VERSION 5.8 ;
BUSBITCHARS "[]" ;
DIVIDERCHAR "/" ;
UNITS
    DATABASE MICRONS 1000 ;
END UNITS

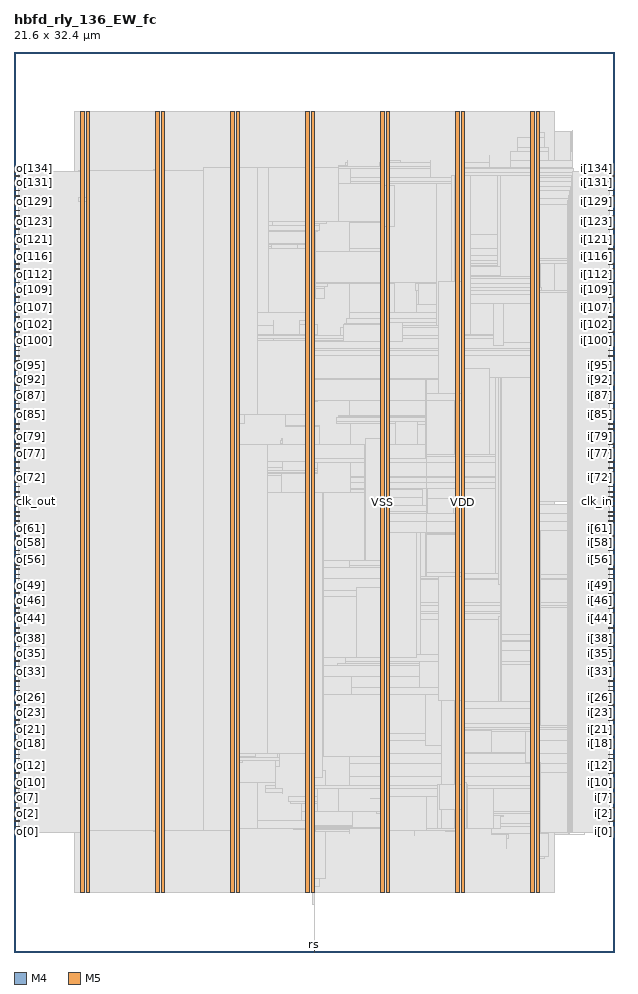
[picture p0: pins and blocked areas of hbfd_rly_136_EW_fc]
MACRO hbfd_rly_136_EW_fc
  FOREIGN hbfd_rly_136_EW_fc 0 0 ;
  CLASS BLOCK ;
  SIZE 21.6 BY 32.4 ;
  PIN clk_in
    DIRECTION INPUT ;
    USE SIGNAL ;
    PORT
      LAYER M4 ;
        RECT  21.408 16.224 21.6 16.248 ;
    END
  END clk_in
  PIN clk_out
    DIRECTION OUTPUT ;
    USE SIGNAL ;
    PORT
      LAYER M4 ;
        RECT  0 16.224 0.192 16.248 ;
    END
  END clk_out
  PIN i[0]
    DIRECTION INPUT ;
    USE SIGNAL ;
    PORT
      LAYER M4 ;
        RECT  21.408 4.32 21.6 4.344 ;
    END
  END i[0]
  PIN i[100]
    DIRECTION INPUT ;
    USE SIGNAL ;
    PORT
      LAYER M4 ;
        RECT  21.408 21.984 21.6 22.008 ;
    END
  END i[100]
  PIN i[101]
    DIRECTION INPUT ;
    USE SIGNAL ;
    PORT
      LAYER M4 ;
        RECT  21.408 22.128 21.6 22.152 ;
    END
  END i[101]
  PIN i[102]
    DIRECTION INPUT ;
    USE SIGNAL ;
    PORT
      LAYER M4 ;
        RECT  21.408 22.32 21.6 22.344 ;
    END
  END i[102]
  PIN i[103]
    DIRECTION INPUT ;
    USE SIGNAL ;
    PORT
      LAYER M4 ;
        RECT  21.408 22.512 21.6 22.536 ;
    END
  END i[103]
  PIN i[104]
    DIRECTION INPUT ;
    USE SIGNAL ;
    PORT
      LAYER M4 ;
        RECT  21.408 22.656 21.6 22.68 ;
    END
  END i[104]
  PIN i[105]
    DIRECTION INPUT ;
    USE SIGNAL ;
    PORT
      LAYER M4 ;
        RECT  21.408 22.848 21.6 22.872 ;
    END
  END i[105]
  PIN i[106]
    DIRECTION INPUT ;
    USE SIGNAL ;
    PORT
      LAYER M4 ;
        RECT  21.408 23.04 21.6 23.064 ;
    END
  END i[106]
  PIN i[107]
    DIRECTION INPUT ;
    USE SIGNAL ;
    PORT
      LAYER M4 ;
        RECT  21.408 23.184 21.6 23.208 ;
    END
  END i[107]
  PIN i[108]
    DIRECTION INPUT ;
    USE SIGNAL ;
    PORT
      LAYER M4 ;
        RECT  21.408 23.376 21.6 23.4 ;
    END
  END i[108]
  PIN i[109]
    DIRECTION INPUT ;
    USE SIGNAL ;
    PORT
      LAYER M4 ;
        RECT  21.408 23.568 21.6 23.592 ;
    END
  END i[109]
  PIN i[10]
    DIRECTION INPUT ;
    USE SIGNAL ;
    PORT
      LAYER M4 ;
        RECT  21.408 6.096 21.6 6.12 ;
    END
  END i[10]
  PIN i[110]
    DIRECTION INPUT ;
    USE SIGNAL ;
    PORT
      LAYER M4 ;
        RECT  21.408 23.712 21.6 23.736 ;
    END
  END i[110]
  PIN i[111]
    DIRECTION INPUT ;
    USE SIGNAL ;
    PORT
      LAYER M4 ;
        RECT  21.408 23.904 21.6 23.928 ;
    END
  END i[111]
  PIN i[112]
    DIRECTION INPUT ;
    USE SIGNAL ;
    PORT
      LAYER M4 ;
        RECT  21.408 24.096 21.6 24.12 ;
    END
  END i[112]
  PIN i[113]
    DIRECTION INPUT ;
    USE SIGNAL ;
    PORT
      LAYER M4 ;
        RECT  21.408 24.24 21.6 24.264 ;
    END
  END i[113]
  PIN i[114]
    DIRECTION INPUT ;
    USE SIGNAL ;
    PORT
      LAYER M4 ;
        RECT  21.408 24.432 21.6 24.456 ;
    END
  END i[114]
  PIN i[115]
    DIRECTION INPUT ;
    USE SIGNAL ;
    PORT
      LAYER M4 ;
        RECT  21.408 24.576 21.6 24.6 ;
    END
  END i[115]
  PIN i[116]
    DIRECTION INPUT ;
    USE SIGNAL ;
    PORT
      LAYER M4 ;
        RECT  21.408 24.768 21.6 24.792 ;
    END
  END i[116]
  PIN i[117]
    DIRECTION INPUT ;
    USE SIGNAL ;
    PORT
      LAYER M4 ;
        RECT  21.408 24.96 21.6 24.984 ;
    END
  END i[117]
  PIN i[118]
    DIRECTION INPUT ;
    USE SIGNAL ;
    PORT
      LAYER M4 ;
        RECT  21.408 25.104 21.6 25.128 ;
    END
  END i[118]
  PIN i[119]
    DIRECTION INPUT ;
    USE SIGNAL ;
    PORT
      LAYER M4 ;
        RECT  21.408 25.296 21.6 25.32 ;
    END
  END i[119]
  PIN i[11]
    DIRECTION INPUT ;
    USE SIGNAL ;
    PORT
      LAYER M4 ;
        RECT  21.408 6.24 21.6 6.264 ;
    END
  END i[11]
  PIN i[120]
    DIRECTION INPUT ;
    USE SIGNAL ;
    PORT
      LAYER M4 ;
        RECT  21.408 25.488 21.6 25.512 ;
    END
  END i[120]
  PIN i[121]
    DIRECTION INPUT ;
    USE SIGNAL ;
    PORT
      LAYER M4 ;
        RECT  21.408 25.632 21.6 25.656 ;
    END
  END i[121]
  PIN i[122]
    DIRECTION INPUT ;
    USE SIGNAL ;
    PORT
      LAYER M4 ;
        RECT  21.408 25.824 21.6 25.848 ;
    END
  END i[122]
  PIN i[123]
    DIRECTION INPUT ;
    USE SIGNAL ;
    PORT
      LAYER M4 ;
        RECT  21.408 26.016 21.6 26.04 ;
    END
  END i[123]
  PIN i[124]
    DIRECTION INPUT ;
    USE SIGNAL ;
    PORT
      LAYER M4 ;
        RECT  21.408 26.16 21.6 26.184 ;
    END
  END i[124]
  PIN i[125]
    DIRECTION INPUT ;
    USE SIGNAL ;
    PORT
      LAYER M4 ;
        RECT  21.408 26.352 21.6 26.376 ;
    END
  END i[125]
  PIN i[126]
    DIRECTION INPUT ;
    USE SIGNAL ;
    PORT
      LAYER M4 ;
        RECT  21.408 26.496 21.6 26.52 ;
    END
  END i[126]
  PIN i[127]
    DIRECTION INPUT ;
    USE SIGNAL ;
    PORT
      LAYER M4 ;
        RECT  21.408 26.688 21.6 26.712 ;
    END
  END i[127]
  PIN i[128]
    DIRECTION INPUT ;
    USE SIGNAL ;
    PORT
      LAYER M4 ;
        RECT  21.408 26.88 21.6 26.904 ;
    END
  END i[128]
  PIN i[129]
    DIRECTION INPUT ;
    USE SIGNAL ;
    PORT
      LAYER M4 ;
        RECT  21.408 27.024 21.6 27.048 ;
    END
  END i[129]
  PIN i[12]
    DIRECTION INPUT ;
    USE SIGNAL ;
    PORT
      LAYER M4 ;
        RECT  21.408 6.432 21.6 6.456 ;
    END
  END i[12]
  PIN i[130]
    DIRECTION INPUT ;
    USE SIGNAL ;
    PORT
      LAYER M4 ;
        RECT  21.408 27.216 21.6 27.24 ;
    END
  END i[130]
  PIN i[131]
    DIRECTION INPUT ;
    USE SIGNAL ;
    PORT
      LAYER M4 ;
        RECT  21.408 27.408 21.6 27.432 ;
    END
  END i[131]
  PIN i[132]
    DIRECTION INPUT ;
    USE SIGNAL ;
    PORT
      LAYER M4 ;
        RECT  21.408 27.552 21.6 27.576 ;
    END
  END i[132]
  PIN i[133]
    DIRECTION INPUT ;
    USE SIGNAL ;
    PORT
      LAYER M4 ;
        RECT  21.408 27.744 21.6 27.768 ;
    END
  END i[133]
  PIN i[134]
    DIRECTION INPUT ;
    USE SIGNAL ;
    PORT
      LAYER M4 ;
        RECT  21.408 27.936 21.6 27.96 ;
    END
  END i[134]
  PIN i[135]
    DIRECTION INPUT ;
    USE SIGNAL ;
    PORT
      LAYER M4 ;
        RECT  21.408 28.08 21.6 28.104 ;
    END
  END i[135]
  PIN i[13]
    DIRECTION INPUT ;
    USE SIGNAL ;
    PORT
      LAYER M4 ;
        RECT  21.408 6.624 21.6 6.648 ;
    END
  END i[13]
  PIN i[14]
    DIRECTION INPUT ;
    USE SIGNAL ;
    PORT
      LAYER M4 ;
        RECT  21.408 6.768 21.6 6.792 ;
    END
  END i[14]
  PIN i[15]
    DIRECTION INPUT ;
    USE SIGNAL ;
    PORT
      LAYER M4 ;
        RECT  21.408 6.96 21.6 6.984 ;
    END
  END i[15]
  PIN i[16]
    DIRECTION INPUT ;
    USE SIGNAL ;
    PORT
      LAYER M4 ;
        RECT  21.408 7.104 21.6 7.128 ;
    END
  END i[16]
  PIN i[17]
    DIRECTION INPUT ;
    USE SIGNAL ;
    PORT
      LAYER M4 ;
        RECT  21.408 7.296 21.6 7.32 ;
    END
  END i[17]
  PIN i[18]
    DIRECTION INPUT ;
    USE SIGNAL ;
    PORT
      LAYER M4 ;
        RECT  21.408 7.488 21.6 7.512 ;
    END
  END i[18]
  PIN i[19]
    DIRECTION INPUT ;
    USE SIGNAL ;
    PORT
      LAYER M4 ;
        RECT  21.408 7.632 21.6 7.656 ;
    END
  END i[19]
  PIN i[1]
    DIRECTION INPUT ;
    USE SIGNAL ;
    PORT
      LAYER M4 ;
        RECT  21.408 4.512 21.6 4.536 ;
    END
  END i[1]
  PIN i[20]
    DIRECTION INPUT ;
    USE SIGNAL ;
    PORT
      LAYER M4 ;
        RECT  21.408 7.824 21.6 7.848 ;
    END
  END i[20]
  PIN i[21]
    DIRECTION INPUT ;
    USE SIGNAL ;
    PORT
      LAYER M4 ;
        RECT  21.408 8.016 21.6 8.04 ;
    END
  END i[21]
  PIN i[22]
    DIRECTION INPUT ;
    USE SIGNAL ;
    PORT
      LAYER M4 ;
        RECT  21.408 8.16 21.6 8.184 ;
    END
  END i[22]
  PIN i[23]
    DIRECTION INPUT ;
    USE SIGNAL ;
    PORT
      LAYER M4 ;
        RECT  21.408 8.352 21.6 8.376 ;
    END
  END i[23]
  PIN i[24]
    DIRECTION INPUT ;
    USE SIGNAL ;
    PORT
      LAYER M4 ;
        RECT  21.408 8.544 21.6 8.568 ;
    END
  END i[24]
  PIN i[25]
    DIRECTION INPUT ;
    USE SIGNAL ;
    PORT
      LAYER M4 ;
        RECT  21.408 8.688 21.6 8.712 ;
    END
  END i[25]
  PIN i[26]
    DIRECTION INPUT ;
    USE SIGNAL ;
    PORT
      LAYER M4 ;
        RECT  21.408 8.88 21.6 8.904 ;
    END
  END i[26]
  PIN i[27]
    DIRECTION INPUT ;
    USE SIGNAL ;
    PORT
      LAYER M4 ;
        RECT  21.408 9.072 21.6 9.096 ;
    END
  END i[27]
  PIN i[28]
    DIRECTION INPUT ;
    USE SIGNAL ;
    PORT
      LAYER M4 ;
        RECT  21.408 9.216 21.6 9.24 ;
    END
  END i[28]
  PIN i[29]
    DIRECTION INPUT ;
    USE SIGNAL ;
    PORT
      LAYER M4 ;
        RECT  21.408 9.408 21.6 9.432 ;
    END
  END i[29]
  PIN i[2]
    DIRECTION INPUT ;
    USE SIGNAL ;
    PORT
      LAYER M4 ;
        RECT  21.408 4.704 21.6 4.728 ;
    END
  END i[2]
  PIN i[30]
    DIRECTION INPUT ;
    USE SIGNAL ;
    PORT
      LAYER M4 ;
        RECT  21.408 9.552 21.6 9.576 ;
    END
  END i[30]
  PIN i[31]
    DIRECTION INPUT ;
    USE SIGNAL ;
    PORT
      LAYER M4 ;
        RECT  21.408 9.744 21.6 9.768 ;
    END
  END i[31]
  PIN i[32]
    DIRECTION INPUT ;
    USE SIGNAL ;
    PORT
      LAYER M4 ;
        RECT  21.408 9.936 21.6 9.96 ;
    END
  END i[32]
  PIN i[33]
    DIRECTION INPUT ;
    USE SIGNAL ;
    PORT
      LAYER M4 ;
        RECT  21.408 10.08 21.6 10.104 ;
    END
  END i[33]
  PIN i[34]
    DIRECTION INPUT ;
    USE SIGNAL ;
    PORT
      LAYER M4 ;
        RECT  21.408 10.272 21.6 10.296 ;
    END
  END i[34]
  PIN i[35]
    DIRECTION INPUT ;
    USE SIGNAL ;
    PORT
      LAYER M4 ;
        RECT  21.408 10.464 21.6 10.488 ;
    END
  END i[35]
  PIN i[36]
    DIRECTION INPUT ;
    USE SIGNAL ;
    PORT
      LAYER M4 ;
        RECT  21.408 10.608 21.6 10.632 ;
    END
  END i[36]
  PIN i[37]
    DIRECTION INPUT ;
    USE SIGNAL ;
    PORT
      LAYER M4 ;
        RECT  21.408 10.8 21.6 10.824 ;
    END
  END i[37]
  PIN i[38]
    DIRECTION INPUT ;
    USE SIGNAL ;
    PORT
      LAYER M4 ;
        RECT  21.408 10.992 21.6 11.016 ;
    END
  END i[38]
  PIN i[39]
    DIRECTION INPUT ;
    USE SIGNAL ;
    PORT
      LAYER M4 ;
        RECT  21.408 11.136 21.6 11.16 ;
    END
  END i[39]
  PIN i[3]
    DIRECTION INPUT ;
    USE SIGNAL ;
    PORT
      LAYER M4 ;
        RECT  21.408 4.848 21.6 4.872 ;
    END
  END i[3]
  PIN i[40]
    DIRECTION INPUT ;
    USE SIGNAL ;
    PORT
      LAYER M4 ;
        RECT  21.408 11.328 21.6 11.352 ;
    END
  END i[40]
  PIN i[41]
    DIRECTION INPUT ;
    USE SIGNAL ;
    PORT
      LAYER M4 ;
        RECT  21.408 11.472 21.6 11.496 ;
    END
  END i[41]
  PIN i[42]
    DIRECTION INPUT ;
    USE SIGNAL ;
    PORT
      LAYER M4 ;
        RECT  21.408 11.664 21.6 11.688 ;
    END
  END i[42]
  PIN i[43]
    DIRECTION INPUT ;
    USE SIGNAL ;
    PORT
      LAYER M4 ;
        RECT  21.408 11.856 21.6 11.88 ;
    END
  END i[43]
  PIN i[44]
    DIRECTION INPUT ;
    USE SIGNAL ;
    PORT
      LAYER M4 ;
        RECT  21.408 12 21.6 12.024 ;
    END
  END i[44]
  PIN i[45]
    DIRECTION INPUT ;
    USE SIGNAL ;
    PORT
      LAYER M4 ;
        RECT  21.408 12.192 21.6 12.216 ;
    END
  END i[45]
  PIN i[46]
    DIRECTION INPUT ;
    USE SIGNAL ;
    PORT
      LAYER M4 ;
        RECT  21.408 12.384 21.6 12.408 ;
    END
  END i[46]
  PIN i[47]
    DIRECTION INPUT ;
    USE SIGNAL ;
    PORT
      LAYER M4 ;
        RECT  21.408 12.528 21.6 12.552 ;
    END
  END i[47]
  PIN i[48]
    DIRECTION INPUT ;
    USE SIGNAL ;
    PORT
      LAYER M4 ;
        RECT  21.408 12.72 21.6 12.744 ;
    END
  END i[48]
  PIN i[49]
    DIRECTION INPUT ;
    USE SIGNAL ;
    PORT
      LAYER M4 ;
        RECT  21.408 12.912 21.6 12.936 ;
    END
  END i[49]
  PIN i[4]
    DIRECTION INPUT ;
    USE SIGNAL ;
    PORT
      LAYER M4 ;
        RECT  21.408 5.04 21.6 5.064 ;
    END
  END i[4]
  PIN i[50]
    DIRECTION INPUT ;
    USE SIGNAL ;
    PORT
      LAYER M4 ;
        RECT  21.408 13.056 21.6 13.08 ;
    END
  END i[50]
  PIN i[51]
    DIRECTION INPUT ;
    USE SIGNAL ;
    PORT
      LAYER M4 ;
        RECT  21.408 13.248 21.6 13.272 ;
    END
  END i[51]
  PIN i[52]
    DIRECTION INPUT ;
    USE SIGNAL ;
    PORT
      LAYER M4 ;
        RECT  21.408 13.44 21.6 13.464 ;
    END
  END i[52]
  PIN i[53]
    DIRECTION INPUT ;
    USE SIGNAL ;
    PORT
      LAYER M4 ;
        RECT  21.408 13.584 21.6 13.608 ;
    END
  END i[53]
  PIN i[54]
    DIRECTION INPUT ;
    USE SIGNAL ;
    PORT
      LAYER M4 ;
        RECT  21.408 13.776 21.6 13.8 ;
    END
  END i[54]
  PIN i[55]
    DIRECTION INPUT ;
    USE SIGNAL ;
    PORT
      LAYER M4 ;
        RECT  21.408 13.92 21.6 13.944 ;
    END
  END i[55]
  PIN i[56]
    DIRECTION INPUT ;
    USE SIGNAL ;
    PORT
      LAYER M4 ;
        RECT  21.408 14.112 21.6 14.136 ;
    END
  END i[56]
  PIN i[57]
    DIRECTION INPUT ;
    USE SIGNAL ;
    PORT
      LAYER M4 ;
        RECT  21.408 14.304 21.6 14.328 ;
    END
  END i[57]
  PIN i[58]
    DIRECTION INPUT ;
    USE SIGNAL ;
    PORT
      LAYER M4 ;
        RECT  21.408 14.448 21.6 14.472 ;
    END
  END i[58]
  PIN i[59]
    DIRECTION INPUT ;
    USE SIGNAL ;
    PORT
      LAYER M4 ;
        RECT  21.408 14.64 21.6 14.664 ;
    END
  END i[59]
  PIN i[5]
    DIRECTION INPUT ;
    USE SIGNAL ;
    PORT
      LAYER M4 ;
        RECT  21.408 5.184 21.6 5.208 ;
    END
  END i[5]
  PIN i[60]
    DIRECTION INPUT ;
    USE SIGNAL ;
    PORT
      LAYER M4 ;
        RECT  21.408 14.832 21.6 14.856 ;
    END
  END i[60]
  PIN i[61]
    DIRECTION INPUT ;
    USE SIGNAL ;
    PORT
      LAYER M4 ;
        RECT  21.408 14.976 21.6 15 ;
    END
  END i[61]
  PIN i[62]
    DIRECTION INPUT ;
    USE SIGNAL ;
    PORT
      LAYER M4 ;
        RECT  21.408 15.168 21.6 15.192 ;
    END
  END i[62]
  PIN i[63]
    DIRECTION INPUT ;
    USE SIGNAL ;
    PORT
      LAYER M4 ;
        RECT  21.408 15.36 21.6 15.384 ;
    END
  END i[63]
  PIN i[64]
    DIRECTION INPUT ;
    USE SIGNAL ;
    PORT
      LAYER M4 ;
        RECT  21.408 15.504 21.6 15.528 ;
    END
  END i[64]
  PIN i[65]
    DIRECTION INPUT ;
    USE SIGNAL ;
    PORT
      LAYER M4 ;
        RECT  21.408 15.696 21.6 15.72 ;
    END
  END i[65]
  PIN i[66]
    DIRECTION INPUT ;
    USE SIGNAL ;
    PORT
      LAYER M4 ;
        RECT  21.408 15.84 21.6 15.864 ;
    END
  END i[66]
  PIN i[67]
    DIRECTION INPUT ;
    USE SIGNAL ;
    PORT
      LAYER M4 ;
        RECT  21.408 16.032 21.6 16.056 ;
    END
  END i[67]
  PIN i[68]
    DIRECTION INPUT ;
    USE SIGNAL ;
    PORT
      LAYER M4 ;
        RECT  21.408 16.368 21.6 16.392 ;
    END
  END i[68]
  PIN i[69]
    DIRECTION INPUT ;
    USE SIGNAL ;
    PORT
      LAYER M4 ;
        RECT  21.408 16.56 21.6 16.584 ;
    END
  END i[69]
  PIN i[6]
    DIRECTION INPUT ;
    USE SIGNAL ;
    PORT
      LAYER M4 ;
        RECT  21.408 5.376 21.6 5.4 ;
    END
  END i[6]
  PIN i[70]
    DIRECTION INPUT ;
    USE SIGNAL ;
    PORT
      LAYER M4 ;
        RECT  21.408 16.752 21.6 16.776 ;
    END
  END i[70]
  PIN i[71]
    DIRECTION INPUT ;
    USE SIGNAL ;
    PORT
      LAYER M4 ;
        RECT  21.408 16.896 21.6 16.92 ;
    END
  END i[71]
  PIN i[72]
    DIRECTION INPUT ;
    USE SIGNAL ;
    PORT
      LAYER M4 ;
        RECT  21.408 17.088 21.6 17.112 ;
    END
  END i[72]
  PIN i[73]
    DIRECTION INPUT ;
    USE SIGNAL ;
    PORT
      LAYER M4 ;
        RECT  21.408 17.28 21.6 17.304 ;
    END
  END i[73]
  PIN i[74]
    DIRECTION INPUT ;
    USE SIGNAL ;
    PORT
      LAYER M4 ;
        RECT  21.408 17.424 21.6 17.448 ;
    END
  END i[74]
  PIN i[75]
    DIRECTION INPUT ;
    USE SIGNAL ;
    PORT
      LAYER M4 ;
        RECT  21.408 17.616 21.6 17.64 ;
    END
  END i[75]
  PIN i[76]
    DIRECTION INPUT ;
    USE SIGNAL ;
    PORT
      LAYER M4 ;
        RECT  21.408 17.808 21.6 17.832 ;
    END
  END i[76]
  PIN i[77]
    DIRECTION INPUT ;
    USE SIGNAL ;
    PORT
      LAYER M4 ;
        RECT  21.408 17.952 21.6 17.976 ;
    END
  END i[77]
  PIN i[78]
    DIRECTION INPUT ;
    USE SIGNAL ;
    PORT
      LAYER M4 ;
        RECT  21.408 18.144 21.6 18.168 ;
    END
  END i[78]
  PIN i[79]
    DIRECTION INPUT ;
    USE SIGNAL ;
    PORT
      LAYER M4 ;
        RECT  21.408 18.288 21.6 18.312 ;
    END
  END i[79]
  PIN i[7]
    DIRECTION INPUT ;
    USE SIGNAL ;
    PORT
      LAYER M4 ;
        RECT  21.408 5.568 21.6 5.592 ;
    END
  END i[7]
  PIN i[80]
    DIRECTION INPUT ;
    USE SIGNAL ;
    PORT
      LAYER M4 ;
        RECT  21.408 18.48 21.6 18.504 ;
    END
  END i[80]
  PIN i[81]
    DIRECTION INPUT ;
    USE SIGNAL ;
    PORT
      LAYER M4 ;
        RECT  21.408 18.672 21.6 18.696 ;
    END
  END i[81]
  PIN i[82]
    DIRECTION INPUT ;
    USE SIGNAL ;
    PORT
      LAYER M4 ;
        RECT  21.408 18.816 21.6 18.84 ;
    END
  END i[82]
  PIN i[83]
    DIRECTION INPUT ;
    USE SIGNAL ;
    PORT
      LAYER M4 ;
        RECT  21.408 19.008 21.6 19.032 ;
    END
  END i[83]
  PIN i[84]
    DIRECTION INPUT ;
    USE SIGNAL ;
    PORT
      LAYER M4 ;
        RECT  21.408 19.2 21.6 19.224 ;
    END
  END i[84]
  PIN i[85]
    DIRECTION INPUT ;
    USE SIGNAL ;
    PORT
      LAYER M4 ;
        RECT  21.408 19.344 21.6 19.368 ;
    END
  END i[85]
  PIN i[86]
    DIRECTION INPUT ;
    USE SIGNAL ;
    PORT
      LAYER M4 ;
        RECT  21.408 19.536 21.6 19.56 ;
    END
  END i[86]
  PIN i[87]
    DIRECTION INPUT ;
    USE SIGNAL ;
    PORT
      LAYER M4 ;
        RECT  21.408 19.728 21.6 19.752 ;
    END
  END i[87]
  PIN i[88]
    DIRECTION INPUT ;
    USE SIGNAL ;
    PORT
      LAYER M4 ;
        RECT  21.408 19.872 21.6 19.896 ;
    END
  END i[88]
  PIN i[89]
    DIRECTION INPUT ;
    USE SIGNAL ;
    PORT
      LAYER M4 ;
        RECT  21.408 20.064 21.6 20.088 ;
    END
  END i[89]
  PIN i[8]
    DIRECTION INPUT ;
    USE SIGNAL ;
    PORT
      LAYER M4 ;
        RECT  21.408 5.712 21.6 5.736 ;
    END
  END i[8]
  PIN i[90]
    DIRECTION INPUT ;
    USE SIGNAL ;
    PORT
      LAYER M4 ;
        RECT  21.408 20.208 21.6 20.232 ;
    END
  END i[90]
  PIN i[91]
    DIRECTION INPUT ;
    USE SIGNAL ;
    PORT
      LAYER M4 ;
        RECT  21.408 20.4 21.6 20.424 ;
    END
  END i[91]
  PIN i[92]
    DIRECTION INPUT ;
    USE SIGNAL ;
    PORT
      LAYER M4 ;
        RECT  21.408 20.592 21.6 20.616 ;
    END
  END i[92]
  PIN i[93]
    DIRECTION INPUT ;
    USE SIGNAL ;
    PORT
      LAYER M4 ;
        RECT  21.408 20.736 21.6 20.76 ;
    END
  END i[93]
  PIN i[94]
    DIRECTION INPUT ;
    USE SIGNAL ;
    PORT
      LAYER M4 ;
        RECT  21.408 20.928 21.6 20.952 ;
    END
  END i[94]
  PIN i[95]
    DIRECTION INPUT ;
    USE SIGNAL ;
    PORT
      LAYER M4 ;
        RECT  21.408 21.12 21.6 21.144 ;
    END
  END i[95]
  PIN i[96]
    DIRECTION INPUT ;
    USE SIGNAL ;
    PORT
      LAYER M4 ;
        RECT  21.408 21.264 21.6 21.288 ;
    END
  END i[96]
  PIN i[97]
    DIRECTION INPUT ;
    USE SIGNAL ;
    PORT
      LAYER M4 ;
        RECT  21.408 21.456 21.6 21.48 ;
    END
  END i[97]
  PIN i[98]
    DIRECTION INPUT ;
    USE SIGNAL ;
    PORT
      LAYER M4 ;
        RECT  21.408 21.648 21.6 21.672 ;
    END
  END i[98]
  PIN i[99]
    DIRECTION INPUT ;
    USE SIGNAL ;
    PORT
      LAYER M4 ;
        RECT  21.408 21.792 21.6 21.816 ;
    END
  END i[99]
  PIN i[9]
    DIRECTION INPUT ;
    USE SIGNAL ;
    PORT
      LAYER M4 ;
        RECT  21.408 5.904 21.6 5.928 ;
    END
  END i[9]
  PIN o[0]
    DIRECTION OUTPUT ;
    USE SIGNAL ;
    PORT
      LAYER M4 ;
        RECT  0 4.32 0.192 4.344 ;
    END
  END o[0]
  PIN o[100]
    DIRECTION OUTPUT ;
    USE SIGNAL ;
    PORT
      LAYER M4 ;
        RECT  0 21.984 0.192 22.008 ;
    END
  END o[100]
  PIN o[101]
    DIRECTION OUTPUT ;
    USE SIGNAL ;
    PORT
      LAYER M4 ;
        RECT  0 22.128 0.192 22.152 ;
    END
  END o[101]
  PIN o[102]
    DIRECTION OUTPUT ;
    USE SIGNAL ;
    PORT
      LAYER M4 ;
        RECT  0 22.32 0.192 22.344 ;
    END
  END o[102]
  PIN o[103]
    DIRECTION OUTPUT ;
    USE SIGNAL ;
    PORT
      LAYER M4 ;
        RECT  0 22.512 0.192 22.536 ;
    END
  END o[103]
  PIN o[104]
    DIRECTION OUTPUT ;
    USE SIGNAL ;
    PORT
      LAYER M4 ;
        RECT  0 22.656 0.192 22.68 ;
    END
  END o[104]
  PIN o[105]
    DIRECTION OUTPUT ;
    USE SIGNAL ;
    PORT
      LAYER M4 ;
        RECT  0 22.848 0.192 22.872 ;
    END
  END o[105]
  PIN o[106]
    DIRECTION OUTPUT ;
    USE SIGNAL ;
    PORT
      LAYER M4 ;
        RECT  0 23.04 0.192 23.064 ;
    END
  END o[106]
  PIN o[107]
    DIRECTION OUTPUT ;
    USE SIGNAL ;
    PORT
      LAYER M4 ;
        RECT  0 23.184 0.192 23.208 ;
    END
  END o[107]
  PIN o[108]
    DIRECTION OUTPUT ;
    USE SIGNAL ;
    PORT
      LAYER M4 ;
        RECT  0 23.376 0.192 23.4 ;
    END
  END o[108]
  PIN o[109]
    DIRECTION OUTPUT ;
    USE SIGNAL ;
    PORT
      LAYER M4 ;
        RECT  0 23.568 0.192 23.592 ;
    END
  END o[109]
  PIN o[10]
    DIRECTION OUTPUT ;
    USE SIGNAL ;
    PORT
      LAYER M4 ;
        RECT  0 6.096 0.192 6.12 ;
    END
  END o[10]
  PIN o[110]
    DIRECTION OUTPUT ;
    USE SIGNAL ;
    PORT
      LAYER M4 ;
        RECT  0 23.712 0.192 23.736 ;
    END
  END o[110]
  PIN o[111]
    DIRECTION OUTPUT ;
    USE SIGNAL ;
    PORT
      LAYER M4 ;
        RECT  0 23.904 0.192 23.928 ;
    END
  END o[111]
  PIN o[112]
    DIRECTION OUTPUT ;
    USE SIGNAL ;
    PORT
      LAYER M4 ;
        RECT  0 24.096 0.192 24.12 ;
    END
  END o[112]
  PIN o[113]
    DIRECTION OUTPUT ;
    USE SIGNAL ;
    PORT
      LAYER M4 ;
        RECT  0 24.24 0.192 24.264 ;
    END
  END o[113]
  PIN o[114]
    DIRECTION OUTPUT ;
    USE SIGNAL ;
    PORT
      LAYER M4 ;
        RECT  0 24.432 0.192 24.456 ;
    END
  END o[114]
  PIN o[115]
    DIRECTION OUTPUT ;
    USE SIGNAL ;
    PORT
      LAYER M4 ;
        RECT  0 24.576 0.192 24.6 ;
    END
  END o[115]
  PIN o[116]
    DIRECTION OUTPUT ;
    USE SIGNAL ;
    PORT
      LAYER M4 ;
        RECT  0 24.768 0.192 24.792 ;
    END
  END o[116]
  PIN o[117]
    DIRECTION OUTPUT ;
    USE SIGNAL ;
    PORT
      LAYER M4 ;
        RECT  0 24.96 0.192 24.984 ;
    END
  END o[117]
  PIN o[118]
    DIRECTION OUTPUT ;
    USE SIGNAL ;
    PORT
      LAYER M4 ;
        RECT  0 25.104 0.192 25.128 ;
    END
  END o[118]
  PIN o[119]
    DIRECTION OUTPUT ;
    USE SIGNAL ;
    PORT
      LAYER M4 ;
        RECT  0 25.296 0.192 25.32 ;
    END
  END o[119]
  PIN o[11]
    DIRECTION OUTPUT ;
    USE SIGNAL ;
    PORT
      LAYER M4 ;
        RECT  0 6.24 0.192 6.264 ;
    END
  END o[11]
  PIN o[120]
    DIRECTION OUTPUT ;
    USE SIGNAL ;
    PORT
      LAYER M4 ;
        RECT  0 25.488 0.192 25.512 ;
    END
  END o[120]
  PIN o[121]
    DIRECTION OUTPUT ;
    USE SIGNAL ;
    PORT
      LAYER M4 ;
        RECT  0 25.632 0.192 25.656 ;
    END
  END o[121]
  PIN o[122]
    DIRECTION OUTPUT ;
    USE SIGNAL ;
    PORT
      LAYER M4 ;
        RECT  0 25.824 0.192 25.848 ;
    END
  END o[122]
  PIN o[123]
    DIRECTION OUTPUT ;
    USE SIGNAL ;
    PORT
      LAYER M4 ;
        RECT  0 26.016 0.192 26.04 ;
    END
  END o[123]
  PIN o[124]
    DIRECTION OUTPUT ;
    USE SIGNAL ;
    PORT
      LAYER M4 ;
        RECT  0 26.16 0.192 26.184 ;
    END
  END o[124]
  PIN o[125]
    DIRECTION OUTPUT ;
    USE SIGNAL ;
    PORT
      LAYER M4 ;
        RECT  0 26.352 0.192 26.376 ;
    END
  END o[125]
  PIN o[126]
    DIRECTION OUTPUT ;
    USE SIGNAL ;
    PORT
      LAYER M4 ;
        RECT  0 26.496 0.192 26.52 ;
    END
  END o[126]
  PIN o[127]
    DIRECTION OUTPUT ;
    USE SIGNAL ;
    PORT
      LAYER M4 ;
        RECT  0 26.688 0.192 26.712 ;
    END
  END o[127]
  PIN o[128]
    DIRECTION OUTPUT ;
    USE SIGNAL ;
    PORT
      LAYER M4 ;
        RECT  0 26.88 0.192 26.904 ;
    END
  END o[128]
  PIN o[129]
    DIRECTION OUTPUT ;
    USE SIGNAL ;
    PORT
      LAYER M4 ;
        RECT  0 27.024 0.192 27.048 ;
    END
  END o[129]
  PIN o[12]
    DIRECTION OUTPUT ;
    USE SIGNAL ;
    PORT
      LAYER M4 ;
        RECT  0 6.432 0.192 6.456 ;
    END
  END o[12]
  PIN o[130]
    DIRECTION OUTPUT ;
    USE SIGNAL ;
    PORT
      LAYER M4 ;
        RECT  0 27.216 0.192 27.24 ;
    END
  END o[130]
  PIN o[131]
    DIRECTION OUTPUT ;
    USE SIGNAL ;
    PORT
      LAYER M4 ;
        RECT  0 27.408 0.192 27.432 ;
    END
  END o[131]
  PIN o[132]
    DIRECTION OUTPUT ;
    USE SIGNAL ;
    PORT
      LAYER M4 ;
        RECT  0 27.552 0.192 27.576 ;
    END
  END o[132]
  PIN o[133]
    DIRECTION OUTPUT ;
    USE SIGNAL ;
    PORT
      LAYER M4 ;
        RECT  0 27.744 0.192 27.768 ;
    END
  END o[133]
  PIN o[134]
    DIRECTION OUTPUT ;
    USE SIGNAL ;
    PORT
      LAYER M4 ;
        RECT  0 27.936 0.192 27.96 ;
    END
  END o[134]
  PIN o[135]
    DIRECTION OUTPUT ;
    USE SIGNAL ;
    PORT
      LAYER M4 ;
        RECT  0 28.08 0.192 28.104 ;
    END
  END o[135]
  PIN o[13]
    DIRECTION OUTPUT ;
    USE SIGNAL ;
    PORT
      LAYER M4 ;
        RECT  0 6.624 0.192 6.648 ;
    END
  END o[13]
  PIN o[14]
    DIRECTION OUTPUT ;
    USE SIGNAL ;
    PORT
      LAYER M4 ;
        RECT  0 6.768 0.192 6.792 ;
    END
  END o[14]
  PIN o[15]
    DIRECTION OUTPUT ;
    USE SIGNAL ;
    PORT
      LAYER M4 ;
        RECT  0 6.96 0.192 6.984 ;
    END
  END o[15]
  PIN o[16]
    DIRECTION OUTPUT ;
    USE SIGNAL ;
    PORT
      LAYER M4 ;
        RECT  0 7.104 0.192 7.128 ;
    END
  END o[16]
  PIN o[17]
    DIRECTION OUTPUT ;
    USE SIGNAL ;
    PORT
      LAYER M4 ;
        RECT  0 7.296 0.192 7.32 ;
    END
  END o[17]
  PIN o[18]
    DIRECTION OUTPUT ;
    USE SIGNAL ;
    PORT
      LAYER M4 ;
        RECT  0 7.488 0.192 7.512 ;
    END
  END o[18]
  PIN o[19]
    DIRECTION OUTPUT ;
    USE SIGNAL ;
    PORT
      LAYER M4 ;
        RECT  0 7.632 0.192 7.656 ;
    END
  END o[19]
  PIN o[1]
    DIRECTION OUTPUT ;
    USE SIGNAL ;
    PORT
      LAYER M4 ;
        RECT  0 4.512 0.192 4.536 ;
    END
  END o[1]
  PIN o[20]
    DIRECTION OUTPUT ;
    USE SIGNAL ;
    PORT
      LAYER M4 ;
        RECT  0 7.824 0.192 7.848 ;
    END
  END o[20]
  PIN o[21]
    DIRECTION OUTPUT ;
    USE SIGNAL ;
    PORT
      LAYER M4 ;
        RECT  0 8.016 0.192 8.04 ;
    END
  END o[21]
  PIN o[22]
    DIRECTION OUTPUT ;
    USE SIGNAL ;
    PORT
      LAYER M4 ;
        RECT  0 8.16 0.192 8.184 ;
    END
  END o[22]
  PIN o[23]
    DIRECTION OUTPUT ;
    USE SIGNAL ;
    PORT
      LAYER M4 ;
        RECT  0 8.352 0.192 8.376 ;
    END
  END o[23]
  PIN o[24]
    DIRECTION OUTPUT ;
    USE SIGNAL ;
    PORT
      LAYER M4 ;
        RECT  0 8.544 0.192 8.568 ;
    END
  END o[24]
  PIN o[25]
    DIRECTION OUTPUT ;
    USE SIGNAL ;
    PORT
      LAYER M4 ;
        RECT  0 8.688 0.192 8.712 ;
    END
  END o[25]
  PIN o[26]
    DIRECTION OUTPUT ;
    USE SIGNAL ;
    PORT
      LAYER M4 ;
        RECT  0 8.88 0.192 8.904 ;
    END
  END o[26]
  PIN o[27]
    DIRECTION OUTPUT ;
    USE SIGNAL ;
    PORT
      LAYER M4 ;
        RECT  0 9.072 0.192 9.096 ;
    END
  END o[27]
  PIN o[28]
    DIRECTION OUTPUT ;
    USE SIGNAL ;
    PORT
      LAYER M4 ;
        RECT  0 9.216 0.192 9.24 ;
    END
  END o[28]
  PIN o[29]
    DIRECTION OUTPUT ;
    USE SIGNAL ;
    PORT
      LAYER M4 ;
        RECT  0 9.408 0.192 9.432 ;
    END
  END o[29]
  PIN o[2]
    DIRECTION OUTPUT ;
    USE SIGNAL ;
    PORT
      LAYER M4 ;
        RECT  0 4.704 0.192 4.728 ;
    END
  END o[2]
  PIN o[30]
    DIRECTION OUTPUT ;
    USE SIGNAL ;
    PORT
      LAYER M4 ;
        RECT  0 9.552 0.192 9.576 ;
    END
  END o[30]
  PIN o[31]
    DIRECTION OUTPUT ;
    USE SIGNAL ;
    PORT
      LAYER M4 ;
        RECT  0 9.744 0.192 9.768 ;
    END
  END o[31]
  PIN o[32]
    DIRECTION OUTPUT ;
    USE SIGNAL ;
    PORT
      LAYER M4 ;
        RECT  0 9.936 0.192 9.96 ;
    END
  END o[32]
  PIN o[33]
    DIRECTION OUTPUT ;
    USE SIGNAL ;
    PORT
      LAYER M4 ;
        RECT  0 10.08 0.192 10.104 ;
    END
  END o[33]
  PIN o[34]
    DIRECTION OUTPUT ;
    USE SIGNAL ;
    PORT
      LAYER M4 ;
        RECT  0 10.272 0.192 10.296 ;
    END
  END o[34]
  PIN o[35]
    DIRECTION OUTPUT ;
    USE SIGNAL ;
    PORT
      LAYER M4 ;
        RECT  0 10.464 0.192 10.488 ;
    END
  END o[35]
  PIN o[36]
    DIRECTION OUTPUT ;
    USE SIGNAL ;
    PORT
      LAYER M4 ;
        RECT  0 10.608 0.192 10.632 ;
    END
  END o[36]
  PIN o[37]
    DIRECTION OUTPUT ;
    USE SIGNAL ;
    PORT
      LAYER M4 ;
        RECT  0 10.8 0.192 10.824 ;
    END
  END o[37]
  PIN o[38]
    DIRECTION OUTPUT ;
    USE SIGNAL ;
    PORT
      LAYER M4 ;
        RECT  0 10.992 0.192 11.016 ;
    END
  END o[38]
  PIN o[39]
    DIRECTION OUTPUT ;
    USE SIGNAL ;
    PORT
      LAYER M4 ;
        RECT  0 11.136 0.192 11.16 ;
    END
  END o[39]
  PIN o[3]
    DIRECTION OUTPUT ;
    USE SIGNAL ;
    PORT
      LAYER M4 ;
        RECT  0 4.848 0.192 4.872 ;
    END
  END o[3]
  PIN o[40]
    DIRECTION OUTPUT ;
    USE SIGNAL ;
    PORT
      LAYER M4 ;
        RECT  0 11.328 0.192 11.352 ;
    END
  END o[40]
  PIN o[41]
    DIRECTION OUTPUT ;
    USE SIGNAL ;
    PORT
      LAYER M4 ;
        RECT  0 11.472 0.192 11.496 ;
    END
  END o[41]
  PIN o[42]
    DIRECTION OUTPUT ;
    USE SIGNAL ;
    PORT
      LAYER M4 ;
        RECT  0 11.664 0.192 11.688 ;
    END
  END o[42]
  PIN o[43]
    DIRECTION OUTPUT ;
    USE SIGNAL ;
    PORT
      LAYER M4 ;
        RECT  0 11.856 0.192 11.88 ;
    END
  END o[43]
  PIN o[44]
    DIRECTION OUTPUT ;
    USE SIGNAL ;
    PORT
      LAYER M4 ;
        RECT  0 12 0.192 12.024 ;
    END
  END o[44]
  PIN o[45]
    DIRECTION OUTPUT ;
    USE SIGNAL ;
    PORT
      LAYER M4 ;
        RECT  0 12.192 0.192 12.216 ;
    END
  END o[45]
  PIN o[46]
    DIRECTION OUTPUT ;
    USE SIGNAL ;
    PORT
      LAYER M4 ;
        RECT  0 12.384 0.192 12.408 ;
    END
  END o[46]
  PIN o[47]
    DIRECTION OUTPUT ;
    USE SIGNAL ;
    PORT
      LAYER M4 ;
        RECT  0 12.528 0.192 12.552 ;
    END
  END o[47]
  PIN o[48]
    DIRECTION OUTPUT ;
    USE SIGNAL ;
    PORT
      LAYER M4 ;
        RECT  0 12.72 0.192 12.744 ;
    END
  END o[48]
  PIN o[49]
    DIRECTION OUTPUT ;
    USE SIGNAL ;
    PORT
      LAYER M4 ;
        RECT  0 12.912 0.192 12.936 ;
    END
  END o[49]
  PIN o[4]
    DIRECTION OUTPUT ;
    USE SIGNAL ;
    PORT
      LAYER M4 ;
        RECT  0 5.04 0.192 5.064 ;
    END
  END o[4]
  PIN o[50]
    DIRECTION OUTPUT ;
    USE SIGNAL ;
    PORT
      LAYER M4 ;
        RECT  0 13.056 0.192 13.08 ;
    END
  END o[50]
  PIN o[51]
    DIRECTION OUTPUT ;
    USE SIGNAL ;
    PORT
      LAYER M4 ;
        RECT  0 13.248 0.192 13.272 ;
    END
  END o[51]
  PIN o[52]
    DIRECTION OUTPUT ;
    USE SIGNAL ;
    PORT
      LAYER M4 ;
        RECT  0 13.44 0.192 13.464 ;
    END
  END o[52]
  PIN o[53]
    DIRECTION OUTPUT ;
    USE SIGNAL ;
    PORT
      LAYER M4 ;
        RECT  0 13.584 0.192 13.608 ;
    END
  END o[53]
  PIN o[54]
    DIRECTION OUTPUT ;
    USE SIGNAL ;
    PORT
      LAYER M4 ;
        RECT  0 13.776 0.192 13.8 ;
    END
  END o[54]
  PIN o[55]
    DIRECTION OUTPUT ;
    USE SIGNAL ;
    PORT
      LAYER M4 ;
        RECT  0 13.92 0.192 13.944 ;
    END
  END o[55]
  PIN o[56]
    DIRECTION OUTPUT ;
    USE SIGNAL ;
    PORT
      LAYER M4 ;
        RECT  0 14.112 0.192 14.136 ;
    END
  END o[56]
  PIN o[57]
    DIRECTION OUTPUT ;
    USE SIGNAL ;
    PORT
      LAYER M4 ;
        RECT  0 14.304 0.192 14.328 ;
    END
  END o[57]
  PIN o[58]
    DIRECTION OUTPUT ;
    USE SIGNAL ;
    PORT
      LAYER M4 ;
        RECT  0 14.448 0.192 14.472 ;
    END
  END o[58]
  PIN o[59]
    DIRECTION OUTPUT ;
    USE SIGNAL ;
    PORT
      LAYER M4 ;
        RECT  0 14.64 0.192 14.664 ;
    END
  END o[59]
  PIN o[5]
    DIRECTION OUTPUT ;
    USE SIGNAL ;
    PORT
      LAYER M4 ;
        RECT  0 5.184 0.192 5.208 ;
    END
  END o[5]
  PIN o[60]
    DIRECTION OUTPUT ;
    USE SIGNAL ;
    PORT
      LAYER M4 ;
        RECT  0 14.832 0.192 14.856 ;
    END
  END o[60]
  PIN o[61]
    DIRECTION OUTPUT ;
    USE SIGNAL ;
    PORT
      LAYER M4 ;
        RECT  0 14.976 0.192 15 ;
    END
  END o[61]
  PIN o[62]
    DIRECTION OUTPUT ;
    USE SIGNAL ;
    PORT
      LAYER M4 ;
        RECT  0 15.168 0.192 15.192 ;
    END
  END o[62]
  PIN o[63]
    DIRECTION OUTPUT ;
    USE SIGNAL ;
    PORT
      LAYER M4 ;
        RECT  0 15.36 0.192 15.384 ;
    END
  END o[63]
  PIN o[64]
    DIRECTION OUTPUT ;
    USE SIGNAL ;
    PORT
      LAYER M4 ;
        RECT  0 15.504 0.192 15.528 ;
    END
  END o[64]
  PIN o[65]
    DIRECTION OUTPUT ;
    USE SIGNAL ;
    PORT
      LAYER M4 ;
        RECT  0 15.696 0.192 15.72 ;
    END
  END o[65]
  PIN o[66]
    DIRECTION OUTPUT ;
    USE SIGNAL ;
    PORT
      LAYER M4 ;
        RECT  0 15.84 0.192 15.864 ;
    END
  END o[66]
  PIN o[67]
    DIRECTION OUTPUT ;
    USE SIGNAL ;
    PORT
      LAYER M4 ;
        RECT  0 16.032 0.192 16.056 ;
    END
  END o[67]
  PIN o[68]
    DIRECTION OUTPUT ;
    USE SIGNAL ;
    PORT
      LAYER M4 ;
        RECT  0 16.368 0.192 16.392 ;
    END
  END o[68]
  PIN o[69]
    DIRECTION OUTPUT ;
    USE SIGNAL ;
    PORT
      LAYER M4 ;
        RECT  0 16.56 0.192 16.584 ;
    END
  END o[69]
  PIN o[6]
    DIRECTION OUTPUT ;
    USE SIGNAL ;
    PORT
      LAYER M4 ;
        RECT  0 5.376 0.192 5.4 ;
    END
  END o[6]
  PIN o[70]
    DIRECTION OUTPUT ;
    USE SIGNAL ;
    PORT
      LAYER M4 ;
        RECT  0 16.752 0.192 16.776 ;
    END
  END o[70]
  PIN o[71]
    DIRECTION OUTPUT ;
    USE SIGNAL ;
    PORT
      LAYER M4 ;
        RECT  0 16.896 0.192 16.92 ;
    END
  END o[71]
  PIN o[72]
    DIRECTION OUTPUT ;
    USE SIGNAL ;
    PORT
      LAYER M4 ;
        RECT  0 17.088 0.192 17.112 ;
    END
  END o[72]
  PIN o[73]
    DIRECTION OUTPUT ;
    USE SIGNAL ;
    PORT
      LAYER M4 ;
        RECT  0 17.28 0.192 17.304 ;
    END
  END o[73]
  PIN o[74]
    DIRECTION OUTPUT ;
    USE SIGNAL ;
    PORT
      LAYER M4 ;
        RECT  0 17.424 0.192 17.448 ;
    END
  END o[74]
  PIN o[75]
    DIRECTION OUTPUT ;
    USE SIGNAL ;
    PORT
      LAYER M4 ;
        RECT  0 17.616 0.192 17.64 ;
    END
  END o[75]
  PIN o[76]
    DIRECTION OUTPUT ;
    USE SIGNAL ;
    PORT
      LAYER M4 ;
        RECT  0 17.808 0.192 17.832 ;
    END
  END o[76]
  PIN o[77]
    DIRECTION OUTPUT ;
    USE SIGNAL ;
    PORT
      LAYER M4 ;
        RECT  0 17.952 0.192 17.976 ;
    END
  END o[77]
  PIN o[78]
    DIRECTION OUTPUT ;
    USE SIGNAL ;
    PORT
      LAYER M4 ;
        RECT  0 18.144 0.192 18.168 ;
    END
  END o[78]
  PIN o[79]
    DIRECTION OUTPUT ;
    USE SIGNAL ;
    PORT
      LAYER M4 ;
        RECT  0 18.288 0.192 18.312 ;
    END
  END o[79]
  PIN o[7]
    DIRECTION OUTPUT ;
    USE SIGNAL ;
    PORT
      LAYER M4 ;
        RECT  0 5.568 0.192 5.592 ;
    END
  END o[7]
  PIN o[80]
    DIRECTION OUTPUT ;
    USE SIGNAL ;
    PORT
      LAYER M4 ;
        RECT  0 18.48 0.192 18.504 ;
    END
  END o[80]
  PIN o[81]
    DIRECTION OUTPUT ;
    USE SIGNAL ;
    PORT
      LAYER M4 ;
        RECT  0 18.672 0.192 18.696 ;
    END
  END o[81]
  PIN o[82]
    DIRECTION OUTPUT ;
    USE SIGNAL ;
    PORT
      LAYER M4 ;
        RECT  0 18.816 0.192 18.84 ;
    END
  END o[82]
  PIN o[83]
    DIRECTION OUTPUT ;
    USE SIGNAL ;
    PORT
      LAYER M4 ;
        RECT  0 19.008 0.192 19.032 ;
    END
  END o[83]
  PIN o[84]
    DIRECTION OUTPUT ;
    USE SIGNAL ;
    PORT
      LAYER M4 ;
        RECT  0 19.2 0.192 19.224 ;
    END
  END o[84]
  PIN o[85]
    DIRECTION OUTPUT ;
    USE SIGNAL ;
    PORT
      LAYER M4 ;
        RECT  0 19.344 0.192 19.368 ;
    END
  END o[85]
  PIN o[86]
    DIRECTION OUTPUT ;
    USE SIGNAL ;
    PORT
      LAYER M4 ;
        RECT  0 19.536 0.192 19.56 ;
    END
  END o[86]
  PIN o[87]
    DIRECTION OUTPUT ;
    USE SIGNAL ;
    PORT
      LAYER M4 ;
        RECT  0 19.728 0.192 19.752 ;
    END
  END o[87]
  PIN o[88]
    DIRECTION OUTPUT ;
    USE SIGNAL ;
    PORT
      LAYER M4 ;
        RECT  0 19.872 0.192 19.896 ;
    END
  END o[88]
  PIN o[89]
    DIRECTION OUTPUT ;
    USE SIGNAL ;
    PORT
      LAYER M4 ;
        RECT  0 20.064 0.192 20.088 ;
    END
  END o[89]
  PIN o[8]
    DIRECTION OUTPUT ;
    USE SIGNAL ;
    PORT
      LAYER M4 ;
        RECT  0 5.712 0.192 5.736 ;
    END
  END o[8]
  PIN o[90]
    DIRECTION OUTPUT ;
    USE SIGNAL ;
    PORT
      LAYER M4 ;
        RECT  0 20.208 0.192 20.232 ;
    END
  END o[90]
  PIN o[91]
    DIRECTION OUTPUT ;
    USE SIGNAL ;
    PORT
      LAYER M4 ;
        RECT  0 20.4 0.192 20.424 ;
    END
  END o[91]
  PIN o[92]
    DIRECTION OUTPUT ;
    USE SIGNAL ;
    PORT
      LAYER M4 ;
        RECT  0 20.592 0.192 20.616 ;
    END
  END o[92]
  PIN o[93]
    DIRECTION OUTPUT ;
    USE SIGNAL ;
    PORT
      LAYER M4 ;
        RECT  0 20.736 0.192 20.76 ;
    END
  END o[93]
  PIN o[94]
    DIRECTION OUTPUT ;
    USE SIGNAL ;
    PORT
      LAYER M4 ;
        RECT  0 20.928 0.192 20.952 ;
    END
  END o[94]
  PIN o[95]
    DIRECTION OUTPUT ;
    USE SIGNAL ;
    PORT
      LAYER M4 ;
        RECT  0 21.12 0.192 21.144 ;
    END
  END o[95]
  PIN o[96]
    DIRECTION OUTPUT ;
    USE SIGNAL ;
    PORT
      LAYER M4 ;
        RECT  0 21.264 0.192 21.288 ;
    END
  END o[96]
  PIN o[97]
    DIRECTION OUTPUT ;
    USE SIGNAL ;
    PORT
      LAYER M4 ;
        RECT  0 21.456 0.192 21.48 ;
    END
  END o[97]
  PIN o[98]
    DIRECTION OUTPUT ;
    USE SIGNAL ;
    PORT
      LAYER M4 ;
        RECT  0 21.648 0.192 21.672 ;
    END
  END o[98]
  PIN o[99]
    DIRECTION OUTPUT ;
    USE SIGNAL ;
    PORT
      LAYER M4 ;
        RECT  0 21.792 0.192 21.816 ;
    END
  END o[99]
  PIN o[9]
    DIRECTION OUTPUT ;
    USE SIGNAL ;
    PORT
      LAYER M4 ;
        RECT  0 5.904 0.192 5.928 ;
    END
  END o[9]
  PIN rs
    DIRECTION INPUT ;
    USE SIGNAL ;
    PORT
      LAYER M5 ;
        RECT  10.8 0 10.824 0.192 ;
    END
  END rs
  PIN VDD
    DIRECTION INOUT ;
    USE POWER ;
    PORT
      LAYER M5 ;
        RECT  18.792 2.151 18.912 30.249 ;
        RECT  16.092 2.151 16.212 30.249 ;
        RECT  13.392 2.151 13.512 30.249 ;
        RECT  10.692 2.151 10.812 30.249 ;
        RECT  7.992 2.151 8.112 30.249 ;
        RECT  5.292 2.151 5.412 30.249 ;
        RECT  2.592 2.151 2.712 30.249 ;
    END
  END VDD
  PIN VSS
    DIRECTION INOUT ;
    USE GROUND ;
    PORT
      LAYER M5 ;
        RECT  18.6 2.137 18.72 30.263 ;
        RECT  15.9 2.137 16.02 30.263 ;
        RECT  13.2 2.137 13.32 30.263 ;
        RECT  10.5 2.137 10.62 30.263 ;
        RECT  7.8 2.137 7.92 30.263 ;
        RECT  5.1 2.137 5.22 30.263 ;
        RECT  2.4 2.137 2.52 30.263 ;
    END
  END VSS
  OBS
    LAYER RVTN ;
     RECT  2.16 2.16 19.44 2.295 ;
     RECT  2.16 2.565 19.44 2.835 ;
     RECT  2.16 3.105 19.44 3.375 ;
     RECT  2.16 3.645 19.44 3.915 ;
     RECT  2.16 4.185 19.44 4.455 ;
     RECT  2.16 4.725 19.44 4.995 ;
     RECT  2.16 5.265 19.44 5.535 ;
     RECT  2.16 5.805 19.44 6.075 ;
     RECT  2.16 6.345 19.44 6.615 ;
     RECT  2.16 6.885 19.44 7.155 ;
     RECT  2.16 7.425 19.44 7.695 ;
     RECT  2.16 7.965 19.44 8.235 ;
     RECT  2.16 8.505 19.44 8.775 ;
     RECT  2.16 9.045 19.44 9.315 ;
     RECT  2.16 9.585 19.44 9.855 ;
     RECT  2.16 10.125 19.44 10.395 ;
     RECT  2.16 10.665 19.44 10.935 ;
     RECT  2.16 11.205 19.44 11.475 ;
     RECT  2.16 11.745 19.44 12.015 ;
     RECT  2.16 12.285 19.44 12.555 ;
     RECT  2.16 12.825 19.44 13.095 ;
     RECT  2.16 13.365 19.44 13.635 ;
     RECT  2.16 13.905 19.44 14.175 ;
     RECT  2.16 14.445 19.44 14.715 ;
     RECT  2.16 14.985 19.44 15.255 ;
     RECT  2.16 15.525 19.44 15.795 ;
     RECT  2.16 16.065 19.44 16.335 ;
     RECT  2.16 16.605 19.44 16.875 ;
     RECT  2.16 17.145 19.44 17.415 ;
     RECT  2.16 17.685 19.44 17.955 ;
     RECT  2.16 18.225 19.44 18.495 ;
     RECT  2.16 18.765 19.44 19.035 ;
     RECT  2.16 19.305 19.44 19.575 ;
     RECT  2.16 19.845 19.44 20.115 ;
     RECT  2.16 20.385 19.44 20.655 ;
     RECT  2.16 20.925 19.44 21.195 ;
     RECT  2.16 21.465 19.44 21.735 ;
     RECT  2.16 22.005 19.44 22.275 ;
     RECT  2.16 22.545 19.44 22.815 ;
     RECT  2.16 23.085 19.44 23.355 ;
     RECT  2.16 23.625 19.44 23.895 ;
     RECT  2.16 24.165 19.44 24.435 ;
     RECT  2.16 24.705 19.44 24.975 ;
     RECT  2.16 25.245 19.44 25.515 ;
     RECT  2.16 25.785 19.44 26.055 ;
     RECT  2.16 26.325 19.44 26.595 ;
     RECT  2.16 26.865 19.44 27.135 ;
     RECT  2.16 27.405 19.44 27.675 ;
     RECT  2.16 27.945 19.44 28.215 ;
     RECT  2.16 28.485 19.44 28.755 ;
     RECT  2.16 29.025 19.44 29.295 ;
     RECT  2.16 29.565 19.44 29.835 ;
     RECT  2.16 30.105 19.44 30.24 ;
    LAYER RVTP ;
     RECT  2.16 2.295 19.44 2.565 ;
     RECT  2.16 2.835 19.44 3.105 ;
     RECT  2.16 3.375 19.44 3.645 ;
     RECT  2.16 3.915 19.44 4.185 ;
     RECT  2.16 4.455 19.44 4.725 ;
     RECT  2.16 4.995 19.44 5.265 ;
     RECT  2.16 5.535 19.44 5.805 ;
     RECT  2.16 6.075 19.44 6.345 ;
     RECT  2.16 6.615 19.44 6.885 ;
     RECT  2.16 7.155 19.44 7.425 ;
     RECT  2.16 7.695 19.44 7.965 ;
     RECT  2.16 8.235 19.44 8.505 ;
     RECT  2.16 8.775 19.44 9.045 ;
     RECT  2.16 9.315 19.44 9.585 ;
     RECT  2.16 9.855 19.44 10.125 ;
     RECT  2.16 10.395 19.44 10.665 ;
     RECT  2.16 10.935 19.44 11.205 ;
     RECT  2.16 11.475 19.44 11.745 ;
     RECT  2.16 12.015 19.44 12.285 ;
     RECT  2.16 12.555 19.44 12.825 ;
     RECT  2.16 13.095 19.44 13.365 ;
     RECT  2.16 13.635 19.44 13.905 ;
     RECT  2.16 14.175 19.44 14.445 ;
     RECT  2.16 14.715 19.44 14.985 ;
     RECT  2.16 15.255 19.44 15.525 ;
     RECT  2.16 15.795 19.44 16.065 ;
     RECT  2.16 16.335 19.44 16.605 ;
     RECT  2.16 16.875 19.44 17.145 ;
     RECT  2.16 17.415 19.44 17.685 ;
     RECT  2.16 17.955 19.44 18.225 ;
     RECT  2.16 18.495 19.44 18.765 ;
     RECT  2.16 19.035 19.44 19.305 ;
     RECT  2.16 19.575 19.44 19.845 ;
     RECT  2.16 20.115 19.44 20.385 ;
     RECT  2.16 20.655 19.44 20.925 ;
     RECT  2.16 21.195 19.44 21.465 ;
     RECT  2.16 21.735 19.44 22.005 ;
     RECT  2.16 22.275 19.44 22.545 ;
     RECT  2.16 22.815 19.44 23.085 ;
     RECT  2.16 23.355 19.44 23.625 ;
     RECT  2.16 23.895 19.44 24.165 ;
     RECT  2.16 24.435 19.44 24.705 ;
     RECT  2.16 24.975 19.44 25.245 ;
     RECT  2.16 25.515 19.44 25.785 ;
     RECT  2.16 26.055 19.44 26.325 ;
     RECT  2.16 26.595 19.44 26.865 ;
     RECT  2.16 27.135 19.44 27.405 ;
     RECT  2.16 27.675 19.44 27.945 ;
     RECT  2.16 28.215 19.44 28.485 ;
     RECT  2.16 28.755 19.44 29.025 ;
     RECT  2.16 29.295 19.44 29.565 ;
     RECT  2.16 29.835 19.44 30.105 ;
    LAYER M1 ;
     RECT  2.16 2.151 19.44 30.249 ;
    LAYER M2 ;
     RECT  0.211 5.814 0.247 6.444 ;
     RECT  0.211 9.396 0.247 10.314 ;
     RECT  0.211 19.008 0.247 19.026 ;
     RECT  0.211 7.326 0.499 7.344 ;
     RECT  0.247 19.008 0.499 19.764 ;
     RECT  0.463 4.464 0.535 4.482 ;
     RECT  0.247 5.706 0.535 6.444 ;
     RECT  0.499 7.326 0.535 7.794 ;
     RECT  0.211 12.798 0.535 13.824 ;
     RECT  0.211 16.776 0.535 16.938 ;
     RECT  0.499 18.27 0.535 19.764 ;
     RECT  0.499 20.7 0.535 20.718 ;
     RECT  0.499 22.788 0.535 22.806 ;
     RECT  0.535 4.428 2.16 4.482 ;
     RECT  0.535 5.544 2.16 6.444 ;
     RECT  0.535 7.326 2.16 7.956 ;
     RECT  0.247 8.856 2.16 10.314 ;
     RECT  0.535 11.376 2.16 11.394 ;
     RECT  0.535 12.456 2.16 13.824 ;
     RECT  0.211 15.336 2.16 15.354 ;
     RECT  0.535 16.506 2.16 20.718 ;
     RECT  0.535 22.176 2.16 22.806 ;
     RECT  0.211 23.796 2.16 24.084 ;
     RECT  0.247 27.108 2.16 27.126 ;
     RECT  0.535 27.918 2.16 27.936 ;
     RECT  2.16 2.151 19.44 30.249 ;
     RECT  19.44 16.884 19.463 25.236 ;
     RECT  19.44 26.028 19.463 29.556 ;
     RECT  19.44 4.23 19.967 16.128 ;
     RECT  19.463 17.082 19.967 25.236 ;
     RECT  19.463 26.028 19.967 26.856 ;
     RECT  19.967 4.23 20.003 4.482 ;
     RECT  19.967 6.318 20.003 14.778 ;
     RECT  19.967 15.768 20.003 16.128 ;
     RECT  19.967 17.082 20.003 22.608 ;
     RECT  19.967 23.67 20.003 24.768 ;
     RECT  19.967 26.298 20.003 26.658 ;
     RECT  20.003 6.318 20.039 6.336 ;
     RECT  20.003 7.704 20.039 8.226 ;
     RECT  20.003 10.71 20.039 10.89 ;
     RECT  20.003 11.826 20.039 12.51 ;
     RECT  20.003 13.446 20.039 14.706 ;
     RECT  20.003 15.84 20.039 16.128 ;
     RECT  20.003 17.082 20.039 18.216 ;
     RECT  20.003 19.278 20.039 19.296 ;
     RECT  20.003 20.088 20.039 20.448 ;
     RECT  20.003 22.05 20.039 22.068 ;
     RECT  20.003 23.67 20.039 23.688 ;
     RECT  20.003 24.48 20.039 24.498 ;
     RECT  19.463 27.756 20.039 29.556 ;
     RECT  20.003 9.36 20.075 9.846 ;
     RECT  20.039 16.038 20.075 16.128 ;
     RECT  20.039 17.082 20.075 17.478 ;
     RECT  20.039 20.088 20.075 20.106 ;
     RECT  20.039 28.998 20.075 29.556 ;
     RECT  20.039 10.791 20.111 10.89 ;
     RECT  20.039 27.756 20.111 28.206 ;
     RECT  20.075 29.538 20.111 29.556 ;
     RECT  20.111 28.188 20.147 28.206 ;
     RECT  20.003 4.23 20.543 4.248 ;
     RECT  20.075 9.63 20.543 9.846 ;
     RECT  20.111 10.872 20.543 10.89 ;
     RECT  20.039 12.492 20.543 12.51 ;
     RECT  20.039 13.446 20.543 14.004 ;
     RECT  20.075 16.11 20.543 16.128 ;
     RECT  20.075 17.082 20.543 17.1 ;
     RECT  20.543 9.63 20.579 9.648 ;
     RECT  20.543 13.446 20.579 13.464 ;
     RECT  21.379 10.296 21.479 10.314 ;
    LAYER M3 ;
     RECT  10.8 1.723 10.818 2.143 ;
     RECT  10.515 2.143 10.818 2.371 ;
     RECT  2.415 2.143 2.505 2.413 ;
     RECT  5.115 2.143 5.205 2.413 ;
     RECT  7.815 2.143 7.905 2.413 ;
     RECT  13.215 2.143 13.305 2.413 ;
     RECT  15.915 2.143 16.005 2.413 ;
     RECT  18.615 2.143 18.705 2.413 ;
     RECT  10.515 2.371 10.998 2.641 ;
     RECT  18.615 2.413 18.897 3.379 ;
     RECT  18.615 3.379 19.098 3.451 ;
     RECT  17.712 3.721 17.73 4.081 ;
     RECT  17.712 4.081 17.802 4.225 ;
     RECT  17.208 4.225 17.802 4.261 ;
     RECT  18.615 3.451 19.242 4.261 ;
     RECT  2.415 2.413 2.697 4.315 ;
     RECT  5.115 2.413 5.397 4.351 ;
     RECT  10.515 2.641 11.214 4.351 ;
     RECT  12.06 4.261 12.078 4.351 ;
     RECT  15.915 2.413 16.197 4.351 ;
     RECT  14.4 4.189 14.418 4.363 ;
     RECT  15.516 4.351 16.197 4.363 ;
     RECT  10.515 4.351 12.078 4.423 ;
     RECT  0.54 4.423 0.558 4.459 ;
     RECT  10.044 4.423 12.078 4.459 ;
     RECT  20.52 4.225 20.538 4.459 ;
     RECT  10.044 4.459 12.186 4.507 ;
     RECT  17.208 4.261 19.242 4.507 ;
     RECT  19.98 4.459 20.538 4.507 ;
     RECT  13.215 2.413 13.497 4.531 ;
     RECT  14.4 4.363 16.197 4.531 ;
     RECT  17.208 4.507 20.538 4.531 ;
     RECT  9.972 4.507 12.186 4.559 ;
     RECT  13.215 4.531 13.554 4.621 ;
     RECT  14.4 4.531 20.538 4.621 ;
     RECT  0.468 4.459 0.558 4.733 ;
     RECT  13.215 4.621 20.538 4.999 ;
     RECT  10.332 4.559 12.186 5.063 ;
     RECT  13.032 4.999 20.538 5.069 ;
     RECT  11.664 5.063 12.186 5.071 ;
     RECT  13.032 5.069 19.998 5.071 ;
     RECT  6.84 4.363 6.858 5.197 ;
     RECT  6.84 5.197 6.93 5.341 ;
     RECT  10.332 5.063 10.926 5.341 ;
     RECT  5.004 4.351 5.397 5.369 ;
     RECT  6.3 5.341 6.93 5.369 ;
     RECT  2.304 4.315 2.697 5.405 ;
     RECT  7.815 2.413 8.097 5.431 ;
     RECT  9.936 5.341 10.926 5.431 ;
     RECT  6.3 5.369 6.894 5.495 ;
     RECT  0.468 4.733 0.486 5.539 ;
     RECT  0.468 5.539 0.558 5.563 ;
     RECT  6.84 5.495 6.894 5.567 ;
     RECT  9.864 5.431 10.926 5.603 ;
     RECT  7.815 5.431 8.766 5.639 ;
     RECT  9.648 5.701 9.666 5.737 ;
     RECT  9.036 5.737 9.666 5.873 ;
     RECT  10.515 5.603 10.926 5.881 ;
     RECT  11.664 5.071 19.998 5.881 ;
     RECT  9.036 5.873 9.414 5.999 ;
     RECT  10.515 5.881 19.998 5.999 ;
     RECT  6.84 5.567 6.858 6.179 ;
     RECT  12.06 5.999 19.998 6.313 ;
     RECT  0.216 5.563 0.558 6.449 ;
     RECT  0.54 6.449 0.558 6.461 ;
     RECT  10.515 5.999 11.214 6.539 ;
     RECT  7.815 5.639 8.097 6.583 ;
     RECT  5.115 5.369 5.397 6.619 ;
     RECT  3.996 6.619 4.014 6.656 ;
     RECT  4.86 6.619 5.397 6.691 ;
     RECT  9.396 5.999 9.414 6.691 ;
     RECT  12.06 6.313 20.034 6.797 ;
     RECT  7.164 6.583 8.097 6.817 ;
     RECT  4.716 6.691 5.397 6.845 ;
     RECT  6.12 6.511 6.282 6.845 ;
     RECT  7.164 6.817 8.226 6.889 ;
     RECT  9.396 6.691 9.558 6.889 ;
     RECT  2.415 5.405 2.697 6.952 ;
     RECT  7.164 6.889 9.558 6.989 ;
     RECT  7.164 6.989 8.694 7.051 ;
     RECT  12.06 6.797 19.998 7.159 ;
     RECT  9.468 6.989 9.558 7.195 ;
     RECT  0.216 7.291 0.234 7.349 ;
     RECT  9.468 7.195 9.63 7.349 ;
     RECT  2.304 6.952 2.697 7.529 ;
     RECT  10.515 6.539 10.797 7.591 ;
     RECT  5.004 6.845 5.397 7.619 ;
     RECT  5.04 7.619 5.397 7.627 ;
     RECT  11.988 7.159 19.998 7.627 ;
     RECT  6.624 7.051 8.694 7.661 ;
     RECT  10.515 7.591 11.25 7.691 ;
     RECT  5.04 7.627 5.67 7.735 ;
     RECT  6.624 7.661 8.442 7.735 ;
     RECT  5.04 7.735 8.442 7.799 ;
     RECT  2.415 7.529 2.697 7.861 ;
     RECT  5.115 7.799 8.442 7.889 ;
     RECT  0.504 7.771 0.522 7.933 ;
     RECT  6.264 7.889 8.442 7.961 ;
     RECT  11.988 7.627 20.034 8.011 ;
     RECT  10.515 7.691 11.106 8.033 ;
     RECT  9.468 7.349 9.486 8.041 ;
     RECT  0.504 7.933 0.558 8.045 ;
     RECT  11.916 8.011 20.034 8.069 ;
     RECT  6.3 7.961 8.442 8.159 ;
     RECT  0.504 8.045 0.522 8.189 ;
     RECT  12.132 8.069 20.034 8.231 ;
     RECT  5.115 7.889 5.49 8.339 ;
     RECT  9.216 8.041 9.486 8.401 ;
     RECT  10.515 8.033 10.926 8.401 ;
     RECT  9.216 8.401 10.926 8.501 ;
     RECT  9.216 8.501 9.774 8.537 ;
     RECT  2.415 7.861 2.79 8.671 ;
     RECT  7.815 8.159 8.442 8.671 ;
     RECT  2.304 8.671 2.79 8.683 ;
     RECT  12.132 8.231 19.998 8.771 ;
     RECT  2.304 8.683 2.862 8.813 ;
     RECT  6.3 8.159 7.038 8.843 ;
     RECT  6.408 8.843 7.038 8.879 ;
     RECT  0.252 8.851 0.27 8.909 ;
     RECT  6.876 8.879 7.038 8.969 ;
     RECT  7.815 8.671 9.09 8.969 ;
     RECT  6.876 8.969 6.966 9.101 ;
     RECT  5.115 8.339 5.397 9.112 ;
     RECT  5.004 9.112 5.397 9.149 ;
     RECT  2.304 8.813 2.754 9.248 ;
     RECT  10.515 8.501 10.926 9.283 ;
     RECT  6.948 9.101 6.966 9.293 ;
     RECT  19.944 8.771 19.998 9.355 ;
     RECT  8.964 8.969 9.09 9.391 ;
     RECT  2.415 9.248 2.754 9.419 ;
     RECT  12.132 8.771 19.206 9.509 ;
     RECT  19.944 9.355 20.07 9.547 ;
     RECT  8.964 9.391 9.666 9.553 ;
     RECT  8.964 9.553 9.702 9.581 ;
     RECT  19.944 9.547 20.538 9.625 ;
     RECT  9.396 9.581 9.702 9.661 ;
     RECT  15.336 9.509 19.206 9.661 ;
     RECT  19.944 9.625 20.574 9.661 ;
     RECT  9.396 9.661 9.738 9.851 ;
     RECT  6.372 9.823 6.75 9.859 ;
     RECT  10.515 9.283 11.07 9.931 ;
     RECT  12.132 9.509 14.598 9.931 ;
     RECT  7.815 8.969 8.097 10.021 ;
     RECT  6.336 9.859 6.75 10.049 ;
     RECT  9.396 9.851 9.486 10.049 ;
     RECT  7.704 10.021 8.097 10.057 ;
     RECT  15.336 9.661 20.574 10.109 ;
     RECT  7.596 10.057 8.334 10.229 ;
     RECT  21.384 10.267 21.402 10.291 ;
     RECT  10.515 9.931 14.598 10.319 ;
     RECT  21.384 10.291 21.474 10.319 ;
     RECT  21.456 10.319 21.474 10.349 ;
     RECT  7.815 10.229 8.334 10.363 ;
     RECT  11.628 10.319 14.598 10.391 ;
     RECT  5.115 9.149 5.397 10.459 ;
     RECT  11.916 10.391 14.598 10.471 ;
     RECT  15.336 10.109 20.106 10.471 ;
     RECT  5.115 10.459 5.49 10.499 ;
     RECT  9.432 10.049 9.486 10.669 ;
     RECT  10.515 10.319 10.854 10.669 ;
     RECT  0.216 9.391 0.234 10.829 ;
     RECT  11.916 10.471 20.106 10.867 ;
     RECT  9.432 10.669 10.854 11.011 ;
     RECT  7.815 10.363 8.586 11.129 ;
     RECT  9.324 11.011 10.854 11.173 ;
     RECT  11.916 10.867 20.538 11.173 ;
     RECT  6.3 11.137 6.822 11.179 ;
     RECT  9.324 11.173 20.538 11.201 ;
     RECT  5.115 10.499 5.397 11.272 ;
     RECT  2.415 9.419 2.697 11.281 ;
     RECT  6.3 11.179 6.858 11.309 ;
     RECT  6.336 11.309 6.354 11.399 ;
     RECT  7.815 11.129 8.478 11.399 ;
     RECT  0.54 11.371 0.558 11.501 ;
     RECT  9.396 11.201 20.538 11.501 ;
     RECT  7.815 11.399 8.154 11.641 ;
     RECT  7.668 11.641 8.154 11.741 ;
     RECT  7.668 11.741 8.097 11.749 ;
     RECT  2.304 11.281 2.697 11.885 ;
     RECT  5.004 11.272 5.397 11.939 ;
     RECT  7.416 11.749 8.097 11.939 ;
     RECT  6.48 12.055 6.498 12.091 ;
     RECT  5.115 11.939 5.397 12.181 ;
     RECT  9.396 11.501 20.034 12.181 ;
     RECT  6.48 12.091 6.858 12.209 ;
     RECT  9.216 12.181 20.034 12.269 ;
     RECT  6.336 12.289 6.354 12.389 ;
     RECT  0.252 12.235 0.27 12.451 ;
     RECT  5.115 12.181 5.49 12.451 ;
     RECT  9.36 12.269 20.034 12.479 ;
     RECT  9.756 12.479 20.034 12.487 ;
     RECT  0.252 12.451 0.558 12.557 ;
     RECT  9.756 12.487 20.538 12.587 ;
     RECT  2.415 11.885 2.697 12.619 ;
     RECT  2.415 12.619 2.79 12.659 ;
     RECT  5.115 12.451 6.138 12.749 ;
     RECT  7.815 11.939 8.097 12.991 ;
     RECT  9.756 12.587 13.77 13.019 ;
     RECT  7.815 12.991 8.622 13.171 ;
     RECT  9.756 13.019 9.774 13.199 ;
     RECT  5.115 12.749 5.397 13.261 ;
     RECT  6.12 12.749 6.138 13.289 ;
     RECT  4.824 13.261 5.397 13.361 ;
     RECT  2.415 12.659 2.697 13.387 ;
     RECT  7.815 13.171 8.766 13.387 ;
     RECT  14.58 12.587 20.538 13.405 ;
     RECT  2.415 13.387 2.862 13.432 ;
     RECT  7.524 13.387 8.766 13.433 ;
     RECT  2.304 13.432 2.862 13.435 ;
     RECT  10.515 13.019 13.77 13.441 ;
     RECT  14.508 13.405 20.538 13.441 ;
     RECT  2.304 13.435 2.97 13.469 ;
     RECT  7.524 13.433 8.154 13.567 ;
     RECT  2.415 13.469 2.97 13.613 ;
     RECT  0.216 12.793 0.234 13.829 ;
     RECT  10.515 13.441 20.574 13.829 ;
     RECT  6.336 13.801 6.354 13.901 ;
     RECT  12.06 13.829 20.574 13.901 ;
     RECT  7.416 13.567 8.154 13.915 ;
     RECT  10.515 13.829 10.926 13.937 ;
     RECT  19.944 13.901 20.574 13.949 ;
     RECT  19.944 13.949 20.538 14.009 ;
     RECT  9 13.945 9.018 14.071 ;
     RECT  7.056 13.915 8.154 14.099 ;
     RECT  7.524 14.099 8.154 14.171 ;
     RECT  7.815 14.171 8.154 14.251 ;
     RECT  9 14.071 9.09 14.251 ;
     RECT  2.415 13.613 2.697 14.341 ;
     RECT  5.115 13.361 5.397 14.341 ;
     RECT  2.415 14.341 2.79 14.381 ;
     RECT  5.115 14.341 5.49 14.381 ;
     RECT  10.515 13.937 10.854 14.44 ;
     RECT  10.332 14.44 10.854 14.449 ;
     RECT  7.815 14.251 9.09 14.485 ;
     RECT  10.116 14.449 10.854 14.485 ;
     RECT  12.06 13.901 19.17 14.635 ;
     RECT  19.944 14.009 20.034 14.635 ;
     RECT  7.815 14.485 10.854 14.675 ;
     RECT  7.815 14.675 9.09 14.819 ;
     RECT  9.036 14.819 9.09 14.909 ;
     RECT  0.252 14.827 0.27 15.053 ;
     RECT  12.06 14.635 20.034 15.061 ;
     RECT  11.808 15.061 20.034 15.101 ;
     RECT  2.415 14.381 2.697 15.151 ;
     RECT  7.815 14.819 8.097 15.151 ;
     RECT  2.304 15.151 2.697 15.163 ;
     RECT  11.808 15.101 12.078 15.179 ;
     RECT  9.936 14.675 10.854 15.251 ;
     RECT  7.488 15.151 8.097 15.259 ;
     RECT  10.515 15.251 10.854 15.259 ;
     RECT  2.304 15.163 2.862 15.293 ;
     RECT  7.2 15.259 8.097 15.331 ;
     RECT  10.515 15.259 10.926 15.359 ;
     RECT  0.216 15.331 0.234 15.389 ;
     RECT  12.888 15.101 20.034 15.499 ;
     RECT  5.115 14.381 5.397 15.691 ;
     RECT  6.696 15.331 8.097 15.691 ;
     RECT  9.072 14.909 9.09 15.691 ;
     RECT  5.004 15.691 5.397 15.728 ;
     RECT  12.06 15.179 12.078 15.791 ;
     RECT  12.888 15.499 20.538 15.791 ;
     RECT  12.888 15.791 14.886 15.871 ;
     RECT  6.696 15.691 9.09 15.899 ;
     RECT  7.488 15.899 9.09 15.989 ;
     RECT  5.115 15.728 5.397 16.027 ;
     RECT  15.804 15.791 20.538 16.097 ;
     RECT  20.52 16.097 20.538 16.133 ;
     RECT  9 15.989 9.09 16.141 ;
     RECT  10.515 15.359 10.854 16.169 ;
     RECT  2.304 15.293 2.697 16.219 ;
     RECT  9 16.141 9.558 16.231 ;
     RECT  10.515 16.169 10.797 16.231 ;
     RECT  2.304 16.219 2.862 16.259 ;
     RECT  6.624 16.141 6.642 16.259 ;
     RECT  5.115 16.027 5.562 16.267 ;
     RECT  2.415 16.259 2.862 16.339 ;
     RECT  9 16.231 10.797 16.349 ;
     RECT  2.415 16.339 2.898 16.529 ;
     RECT  7.488 15.989 8.19 16.529 ;
     RECT  15.804 16.097 19.458 16.573 ;
     RECT  0.54 16.501 0.558 16.589 ;
     RECT  12.096 15.871 14.886 16.645 ;
     RECT  12.096 16.645 14.994 16.681 ;
     RECT  15.768 16.573 19.458 16.681 ;
     RECT  12.096 16.681 19.458 16.891 ;
     RECT  4.176 16.891 4.194 17.041 ;
     RECT  5.115 16.267 6.246 17.041 ;
     RECT  4.176 17.041 6.246 17.069 ;
     RECT  12.096 16.891 19.962 17.077 ;
     RECT  0.216 16.747 0.234 17.117 ;
     RECT  12.096 17.077 20.538 17.117 ;
     RECT  9 16.349 9.63 17.149 ;
     RECT  8.964 17.149 9.63 17.221 ;
     RECT  10.515 16.349 10.797 17.221 ;
     RECT  4.32 17.069 5.454 17.249 ;
     RECT  8.964 17.221 10.926 17.249 ;
     RECT  2.415 16.529 2.862 17.275 ;
     RECT  7.74 16.529 8.118 17.311 ;
     RECT  9.108 17.249 10.926 17.339 ;
     RECT  7.74 17.311 8.334 17.411 ;
     RECT  10.476 17.339 10.926 17.411 ;
     RECT  6.336 17.323 6.858 17.419 ;
     RECT  7.74 17.411 8.097 17.419 ;
     RECT  9.108 17.339 9.666 17.453 ;
     RECT  10.515 17.411 10.926 17.617 ;
     RECT  12.096 17.117 20.07 17.617 ;
     RECT  2.304 17.275 2.862 17.681 ;
     RECT  5.004 17.249 5.454 17.789 ;
     RECT  2.304 17.681 2.697 17.837 ;
     RECT  10.515 17.617 20.07 17.837 ;
     RECT  5.115 17.789 5.454 18.121 ;
     RECT  6.336 17.419 8.097 18.121 ;
     RECT  10.515 17.837 20.034 18.149 ;
     RECT  5.115 18.121 8.097 18.221 ;
     RECT  14.508 18.149 20.034 18.221 ;
     RECT  0.54 17.653 0.558 18.265 ;
     RECT  9.648 17.453 9.666 18.265 ;
     RECT  9.612 18.265 9.666 18.301 ;
     RECT  9.576 18.301 9.666 18.419 ;
     RECT  9.612 18.419 9.666 18.491 ;
     RECT  0.504 18.265 0.558 18.667 ;
     RECT  0.216 18.667 0.558 18.845 ;
     RECT  10.515 18.149 10.998 18.931 ;
     RECT  9.756 18.931 10.998 18.959 ;
     RECT  14.508 18.221 19.998 19.003 ;
     RECT  0.216 18.845 0.522 19.031 ;
     RECT  6.192 18.221 6.858 19.039 ;
     RECT  7.815 18.221 8.097 19.039 ;
     RECT  12.096 18.149 13.734 19.039 ;
     RECT  14.508 19.003 20.034 19.103 ;
     RECT  11.592 19.039 13.734 19.111 ;
     RECT  14.508 19.103 19.17 19.111 ;
     RECT  6.12 19.039 6.858 19.139 ;
     RECT  0.252 19.031 0.522 19.229 ;
     RECT  11.592 19.111 19.17 19.229 ;
     RECT  11.664 19.229 19.17 19.277 ;
     RECT  11.664 19.277 19.098 19.301 ;
     RECT  7.815 19.039 8.298 19.471 ;
     RECT  7.815 19.471 8.694 19.643 ;
     RECT  7.815 19.643 8.37 19.679 ;
     RECT  7.815 19.679 8.154 19.769 ;
     RECT  9.756 18.959 10.797 19.813 ;
     RECT  19.944 19.103 20.034 19.867 ;
     RECT  6.552 19.139 6.57 19.949 ;
     RECT  9.756 19.813 10.926 20.011 ;
     RECT  12.06 19.301 19.098 20.059 ;
     RECT  19.944 19.867 20.07 20.059 ;
     RECT  12.06 20.059 20.07 20.111 ;
     RECT  0.252 19.229 0.27 20.203 ;
     RECT  9.108 20.011 10.926 20.281 ;
     RECT  0.216 20.203 0.27 20.333 ;
     RECT  12.06 20.111 20.034 20.453 ;
     RECT  9.108 20.281 11.106 20.461 ;
     RECT  12.06 20.453 19.998 20.461 ;
     RECT  3.996 20.395 4.014 20.579 ;
     RECT  9.108 20.461 19.998 20.579 ;
     RECT  7.815 19.769 8.097 20.623 ;
     RECT  9.828 20.579 19.998 20.651 ;
     RECT  7.308 20.623 8.097 20.659 ;
     RECT  2.415 17.837 2.697 20.695 ;
     RECT  0.504 20.353 0.558 20.765 ;
     RECT  2.415 20.695 2.862 20.849 ;
     RECT  6.912 20.659 8.766 20.849 ;
     RECT  7.02 20.849 8.766 20.921 ;
     RECT  7.02 20.921 8.694 20.993 ;
     RECT  7.02 20.993 8.406 21.029 ;
     RECT  0.504 20.765 0.522 21.293 ;
     RECT  10.224 20.651 19.998 21.469 ;
     RECT  2.415 20.849 2.697 21.631 ;
     RECT  5.115 18.221 5.397 21.631 ;
     RECT  7.02 21.029 8.097 21.643 ;
     RECT  10.008 21.469 19.998 21.643 ;
     RECT  10.008 21.643 20.034 21.739 ;
     RECT  5.004 21.631 5.397 21.787 ;
     RECT  5.004 21.787 5.562 21.901 ;
     RECT  9.324 21.739 20.034 22.073 ;
     RECT  5.004 21.901 5.706 22.081 ;
     RECT  6.84 21.643 8.097 22.081 ;
     RECT  9.324 22.073 19.998 22.081 ;
     RECT  5.004 22.081 5.994 22.199 ;
     RECT  6.84 22.081 19.998 22.199 ;
     RECT  6.84 22.199 10.926 22.235 ;
     RECT  11.736 22.199 19.998 22.469 ;
     RECT  6.84 22.235 9.342 22.541 ;
     RECT  10.26 22.235 10.926 22.577 ;
     RECT  11.88 22.469 19.998 22.613 ;
     RECT  6.84 22.541 8.442 22.637 ;
     RECT  5.004 22.199 5.397 22.649 ;
     RECT  7.38 22.637 8.442 22.649 ;
     RECT  2.304 21.631 2.697 22.685 ;
     RECT  9.324 22.541 9.342 22.739 ;
     RECT  10.26 22.577 10.797 22.739 ;
     RECT  7.596 22.649 8.442 22.775 ;
     RECT  0.54 22.171 0.558 22.783 ;
     RECT  11.952 22.613 19.998 22.811 ;
     RECT  0.504 22.783 0.558 22.877 ;
     RECT  7.776 22.775 8.442 22.919 ;
     RECT  12.06 22.811 19.998 23.009 ;
     RECT  9.468 23.035 9.702 23.081 ;
     RECT  0.504 22.877 0.522 23.179 ;
     RECT  14.472 23.009 19.998 23.315 ;
     RECT  0.216 23.179 0.522 23.405 ;
     RECT  10.515 22.739 10.797 23.521 ;
     RECT  3.996 23.275 4.014 23.549 ;
     RECT  15.372 23.315 19.998 23.665 ;
     RECT  9.468 23.081 9.522 23.791 ;
     RECT  15.372 23.665 20.034 23.819 ;
     RECT  14.472 23.315 14.562 23.827 ;
     RECT  10.515 23.521 11.178 23.899 ;
     RECT  15.372 23.819 18.99 23.927 ;
     RECT  10.26 23.899 11.178 23.971 ;
     RECT  10.26 23.971 11.286 24.061 ;
     RECT  12.06 23.009 13.698 24.061 ;
     RECT  14.436 23.827 14.562 24.061 ;
     RECT  15.372 23.927 18.954 24.061 ;
     RECT  0.216 23.405 0.234 24.089 ;
     RECT  7.776 22.919 8.097 24.169 ;
     RECT  9.432 23.791 9.522 24.205 ;
     RECT  2.415 22.685 2.697 24.232 ;
     RECT  5.115 22.649 5.397 24.232 ;
     RECT  7.2 24.169 8.097 24.235 ;
     RECT  10.26 24.061 13.698 24.241 ;
     RECT  14.436 24.061 18.954 24.241 ;
     RECT  6.84 24.235 8.097 24.269 ;
     RECT  6.84 24.269 6.858 24.331 ;
     RECT  9.324 24.205 9.522 24.331 ;
     RECT  10.26 24.241 18.954 24.331 ;
     RECT  7.596 24.269 8.097 24.359 ;
     RECT  9.324 24.331 18.954 24.359 ;
     RECT  9.324 24.359 10.998 24.413 ;
     RECT  6.66 24.331 6.858 24.431 ;
     RECT  9.324 24.413 9.414 24.431 ;
     RECT  7.74 24.359 8.097 24.781 ;
     RECT  11.736 24.359 18.954 24.781 ;
     RECT  19.944 23.819 20.034 24.781 ;
     RECT  10.188 24.413 10.998 24.797 ;
     RECT  2.304 24.232 2.697 24.809 ;
     RECT  5.004 24.232 5.397 24.809 ;
     RECT  10.188 24.797 10.962 24.809 ;
     RECT  11.736 24.781 20.034 24.899 ;
     RECT  7.74 24.781 8.37 24.989 ;
     RECT  11.772 24.899 20.034 25.079 ;
     RECT  2.415 24.809 2.697 25.141 ;
     RECT  2.415 25.141 2.79 25.147 ;
     RECT  6.84 24.431 6.858 25.195 ;
     RECT  6.732 25.195 6.858 25.243 ;
     RECT  7.74 24.989 8.154 25.243 ;
     RECT  2.415 25.147 2.862 25.277 ;
     RECT  12.06 25.079 20.034 25.325 ;
     RECT  9.252 24.709 9.27 25.411 ;
     RECT  6.732 25.243 8.154 25.439 ;
     RECT  7.815 25.439 8.154 25.475 ;
     RECT  9.108 25.411 9.27 25.483 ;
     RECT  10.188 24.809 10.854 25.483 ;
     RECT  9.108 25.483 10.854 25.517 ;
     RECT  5.115 24.809 5.397 25.579 ;
     RECT  2.415 25.277 2.79 25.619 ;
     RECT  5.115 25.579 5.49 25.619 ;
     RECT  6.732 25.439 7.074 25.619 ;
     RECT  6.732 25.619 6.75 25.717 ;
     RECT  6.624 25.717 6.75 25.817 ;
     RECT  6.624 25.817 6.642 25.889 ;
     RECT  9.144 25.517 10.854 25.951 ;
     RECT  7.815 25.475 8.118 25.979 ;
     RECT  9.144 25.951 10.926 25.987 ;
     RECT  9.144 25.987 10.998 26.159 ;
     RECT  10.515 26.159 10.998 26.221 ;
     RECT  12.06 25.325 19.998 26.249 ;
     RECT  12.06 26.249 13.698 26.285 ;
     RECT  10.515 26.221 11.25 26.321 ;
     RECT  2.415 25.619 2.697 26.491 ;
     RECT  7.815 25.979 8.097 26.491 ;
     RECT  9.144 26.159 9.306 26.519 ;
     RECT  7.704 26.491 8.097 26.527 ;
     RECT  9.144 26.519 9.27 26.527 ;
     RECT  2.304 26.491 2.862 26.528 ;
     RECT  10.515 26.321 11.214 26.591 ;
     RECT  2.415 26.528 2.862 26.621 ;
     RECT  10.515 26.591 11.178 26.627 ;
     RECT  7.596 26.527 8.097 26.699 ;
     RECT  8.964 26.527 9.27 26.699 ;
     RECT  10.515 26.627 11.07 26.789 ;
     RECT  12.096 26.285 13.698 27.139 ;
     RECT  14.472 26.249 19.998 27.139 ;
     RECT  9.108 26.699 9.27 27.301 ;
     RECT  9.108 27.301 9.342 27.329 ;
     RECT  10.515 26.789 10.998 27.403 ;
     RECT  12.096 27.139 19.998 27.403 ;
     RECT  9.324 27.329 9.342 27.473 ;
     RECT  7.815 26.699 8.097 27.481 ;
     RECT  0.252 27.103 0.27 27.547 ;
     RECT  12.096 27.403 20.034 27.547 ;
     RECT  0.216 27.547 0.27 27.677 ;
     RECT  12.096 27.547 20.07 27.739 ;
     RECT  6.3 27.715 6.318 27.751 ;
     RECT  10.476 27.403 10.998 27.841 ;
     RECT  6.3 27.751 6.93 27.869 ;
     RECT  7.776 27.481 8.097 27.869 ;
     RECT  12.096 27.739 20.106 27.869 ;
     RECT  10.476 27.841 11.322 27.913 ;
     RECT  10.224 27.913 11.322 27.941 ;
     RECT  0.54 27.913 0.558 27.965 ;
     RECT  15.768 27.869 20.106 27.965 ;
     RECT  10.224 27.941 10.818 28.049 ;
     RECT  2.415 26.621 2.697 28.075 ;
     RECT  15.915 27.965 20.106 28.075 ;
     RECT  5.115 25.619 5.397 28.111 ;
     RECT  2.304 28.075 2.697 28.139 ;
     RECT  10.296 28.049 10.818 28.139 ;
     RECT  5.004 28.111 5.397 28.157 ;
     RECT  10.515 28.139 10.818 28.211 ;
     RECT  15.915 28.075 20.142 28.211 ;
     RECT  12.096 27.869 14.994 28.219 ;
     RECT  15.915 28.211 20.106 28.247 ;
     RECT  6.84 27.869 6.858 28.253 ;
     RECT  11.664 28.219 14.994 28.283 ;
     RECT  11.664 28.283 12.006 28.319 ;
     RECT  11.916 28.319 12.006 28.409 ;
     RECT  13.14 28.283 14.994 28.409 ;
     RECT  15.915 28.247 17.118 28.409 ;
     RECT  11.988 28.409 12.006 28.481 ;
     RECT  13.215 28.409 13.914 28.481 ;
     RECT  14.976 28.409 14.994 28.481 ;
     RECT  17.856 28.247 20.106 28.481 ;
     RECT  17.1 28.409 17.118 28.679 ;
     RECT  17.856 28.481 19.242 28.823 ;
     RECT  20.016 28.481 20.106 28.823 ;
     RECT  18.108 28.823 19.242 28.949 ;
     RECT  20.052 28.823 20.106 29.021 ;
     RECT  18.108 28.949 19.098 29.327 ;
     RECT  18.615 29.327 19.098 29.489 ;
     RECT  20.088 29.021 20.106 29.561 ;
     RECT  2.415 28.139 2.697 29.987 ;
     RECT  5.115 28.157 5.397 29.987 ;
     RECT  7.815 27.869 8.097 29.987 ;
     RECT  10.515 28.211 10.797 29.987 ;
     RECT  13.215 28.481 13.497 29.987 ;
     RECT  15.915 28.409 16.197 29.987 ;
     RECT  18.615 29.489 18.897 29.987 ;
     RECT  2.415 29.987 2.505 30.257 ;
     RECT  5.115 29.987 5.205 30.257 ;
     RECT  7.815 29.987 7.905 30.257 ;
     RECT  10.515 29.987 10.605 30.257 ;
     RECT  13.215 29.987 13.305 30.257 ;
     RECT  15.915 29.987 16.005 30.257 ;
     RECT  18.615 29.987 18.705 30.257 ;
    LAYER M4 ;
     RECT  0.156 4.32 2.408 28.104 ;
     RECT  2.408 2.148 2.512 30.252 ;
     RECT  2.512 2.418 2.704 29.982 ;
     RECT  2.704 4.368 5.108 28.152 ;
     RECT  5.108 2.148 5.212 30.252 ;
     RECT  5.212 2.418 5.404 29.982 ;
     RECT  5.404 4.368 6.829 28.152 ;
     RECT  6.829 4.368 7.808 28.248 ;
     RECT  7.808 2.148 7.912 30.252 ;
     RECT  7.912 2.418 8.104 29.982 ;
     RECT  8.104 4.464 8.777 6.12 ;
     RECT  8.104 19.344 8.777 28.248 ;
     RECT  8.104 7.152 9.137 18.264 ;
     RECT  8.777 23.04 9.173 28.248 ;
     RECT  8.777 6.096 9.425 6.12 ;
     RECT  8.777 4.464 10.508 4.728 ;
     RECT  9.137 7.152 10.508 16.536 ;
     RECT  9.137 17.664 10.508 18.264 ;
     RECT  8.777 19.344 10.508 22.008 ;
     RECT  9.173 23.04 10.508 25.32 ;
     RECT  9.173 26.304 10.508 28.248 ;
     RECT  10.508 2.148 10.612 30.252 ;
     RECT  10.612 2.148 10.748 29.982 ;
     RECT  10.748 1.728 10.804 29.982 ;
     RECT  10.804 4.368 10.829 4.728 ;
     RECT  10.804 1.728 10.835 1.752 ;
     RECT  10.829 4.368 10.865 4.488 ;
     RECT  10.804 23.568 10.865 25.224 ;
     RECT  10.804 6.288 11.117 16.536 ;
     RECT  11.117 7.056 11.153 16.536 ;
     RECT  10.804 26.304 11.693 28.248 ;
     RECT  10.804 21.984 11.869 22.008 ;
     RECT  11.153 10.608 12.337 12.792 ;
     RECT  11.153 14.112 12.625 16.536 ;
     RECT  10.804 17.76 12.625 18.264 ;
     RECT  12.625 14.112 12.661 18.264 ;
     RECT  10.865 4.464 13.208 4.488 ;
     RECT  12.841 5.52 13.208 5.544 ;
     RECT  11.153 7.056 13.208 9.288 ;
     RECT  12.337 10.608 13.208 13.128 ;
     RECT  12.661 14.112 13.208 18.504 ;
     RECT  10.804 19.872 13.208 20.616 ;
     RECT  11.869 21.984 13.208 22.584 ;
     RECT  10.865 24.096 13.208 25.224 ;
     RECT  11.693 26.304 13.208 27.672 ;
     RECT  13.208 2.148 13.312 30.252 ;
     RECT  13.312 2.418 13.504 29.982 ;
     RECT  13.504 21.984 13.997 22.68 ;
     RECT  13.504 10.608 14.501 15.096 ;
     RECT  14.501 10.704 14.645 15.096 ;
     RECT  13.504 16.08 14.713 16.344 ;
     RECT  14.645 13.536 14.809 15.096 ;
     RECT  13.504 7.872 14.821 9.288 ;
     RECT  13.504 17.76 14.821 18.264 ;
     RECT  13.504 19.872 14.821 20.616 ;
     RECT  13.504 4.368 14.861 5.592 ;
     RECT  14.821 17.76 14.861 20.616 ;
     RECT  14.809 13.536 14.867 15.048 ;
     RECT  14.713 16.08 14.897 16.68 ;
     RECT  13.997 22.56 15.212 22.68 ;
     RECT  13.504 24.096 15.212 27.672 ;
     RECT  14.861 4.464 15.26 5.592 ;
     RECT  15.26 4.464 15.397 6.024 ;
     RECT  14.821 7.44 15.397 9.288 ;
     RECT  15.212 22.56 15.757 27.672 ;
     RECT  15.397 4.464 15.865 9.288 ;
     RECT  14.645 10.704 15.865 11.976 ;
     RECT  14.861 17.904 15.865 20.616 ;
     RECT  15.757 22.56 15.865 27.96 ;
     RECT  15.865 4.464 15.908 11.976 ;
     RECT  14.867 13.632 15.908 15.048 ;
     RECT  14.897 16.32 15.908 16.68 ;
     RECT  15.865 17.904 15.908 21 ;
     RECT  15.865 22.224 15.908 27.96 ;
     RECT  15.908 2.148 16.012 30.252 ;
     RECT  16.012 2.418 16.204 29.982 ;
     RECT  16.204 4.464 16.301 6.12 ;
     RECT  16.301 4.464 16.337 6.024 ;
     RECT  16.204 22.224 16.445 27.96 ;
     RECT  16.204 17.904 17.129 21 ;
     RECT  16.204 7.2 17.201 7.992 ;
     RECT  16.445 22.224 17.269 23.352 ;
     RECT  16.337 4.464 17.273 5.88 ;
     RECT  16.204 13.632 17.341 16.68 ;
     RECT  17.129 17.904 17.341 20.664 ;
     RECT  16.445 24.672 17.413 24.696 ;
     RECT  16.445 25.824 17.413 27.96 ;
     RECT  16.204 9.024 17.449 11.976 ;
     RECT  17.341 13.632 17.449 20.664 ;
     RECT  17.449 9.024 17.521 12.072 ;
     RECT  17.449 13.248 17.521 20.664 ;
     RECT  17.413 24.672 17.521 27.96 ;
     RECT  17.273 4.464 17.525 4.92 ;
     RECT  17.521 9.024 17.561 20.664 ;
     RECT  17.525 4.896 17.633 4.92 ;
     RECT  17.269 21.84 17.633 23.352 ;
     RECT  17.201 7.2 18.421 7.944 ;
     RECT  18.421 6.816 18.608 7.944 ;
     RECT  17.561 9.024 18.608 10.344 ;
     RECT  17.561 11.424 18.608 20.664 ;
     RECT  17.633 21.936 18.608 23.352 ;
     RECT  17.521 24.336 18.608 27.96 ;
     RECT  18.608 2.148 18.712 30.252 ;
     RECT  18.712 2.418 18.904 29.982 ;
     RECT  18.904 4.32 18.965 6.84 ;
     RECT  18.904 8.16 18.965 15.192 ;
     RECT  18.965 4.32 19.933 6.456 ;
     RECT  18.965 8.16 19.933 12.408 ;
     RECT  18.965 13.584 19.933 15.192 ;
     RECT  18.904 16.224 19.933 23.736 ;
     RECT  18.904 24.96 19.933 26.904 ;
     RECT  19.933 4.32 19.969 27.048 ;
     RECT  19.969 4.32 20.005 27.24 ;
     RECT  20.005 4.32 20.041 27.432 ;
     RECT  20.041 4.32 20.077 27.576 ;
     RECT  20.077 4.32 20.113 27.96 ;
     RECT  20.113 4.32 21.42 28.104 ;
     RECT  21.42 10.32 21.485 10.344 ;
    LAYER M5 ;
     RECT  10.8 0.144 10.824 1.763 ;
     RECT  10.8 1.763 10.812 2.137 ;
     RECT  2.4 2.137 2.52 2.151 ;
     RECT  5.1 2.137 5.22 2.151 ;
     RECT  7.8 2.137 7.92 2.151 ;
     RECT  13.2 2.137 13.32 2.151 ;
     RECT  15.9 2.137 16.02 2.151 ;
     RECT  18.6 2.137 18.72 2.151 ;
     RECT  15.9 2.151 16.212 5.125 ;
     RECT  15.312 5.125 16.212 6.035 ;
     RECT  15.9 6.035 16.212 9.061 ;
     RECT  15.264 9.061 16.212 13.525 ;
     RECT  14.832 13.525 16.212 13.667 ;
     RECT  14.832 13.667 14.856 19.861 ;
     RECT  15.9 13.667 16.212 19.861 ;
     RECT  14.832 19.861 16.212 20.099 ;
     RECT  15.264 20.099 16.212 24.131 ;
     RECT  13.2 2.151 13.512 26.101 ;
     RECT  2.4 2.151 2.712 27.013 ;
     RECT  2.304 27.013 2.712 27.155 ;
     RECT  13.2 26.101 13.704 27.587 ;
     RECT  2.4 27.155 2.712 30.249 ;
     RECT  5.1 2.151 5.412 30.249 ;
     RECT  7.8 2.151 8.112 30.249 ;
     RECT  10.5 2.137 10.812 30.249 ;
     RECT  13.2 27.587 13.512 30.249 ;
     RECT  15.9 24.131 16.212 30.249 ;
     RECT  18.6 2.151 18.912 30.249 ;
     RECT  2.4 30.249 2.52 30.263 ;
     RECT  5.1 30.249 5.22 30.263 ;
     RECT  7.8 30.249 7.92 30.263 ;
     RECT  10.5 30.249 10.62 30.263 ;
     RECT  13.2 30.249 13.32 30.263 ;
     RECT  15.9 30.249 16.02 30.263 ;
     RECT  18.6 30.249 18.72 30.263 ;
  END
END hbfd_rly_136_EW_fc
END LIBRARY
